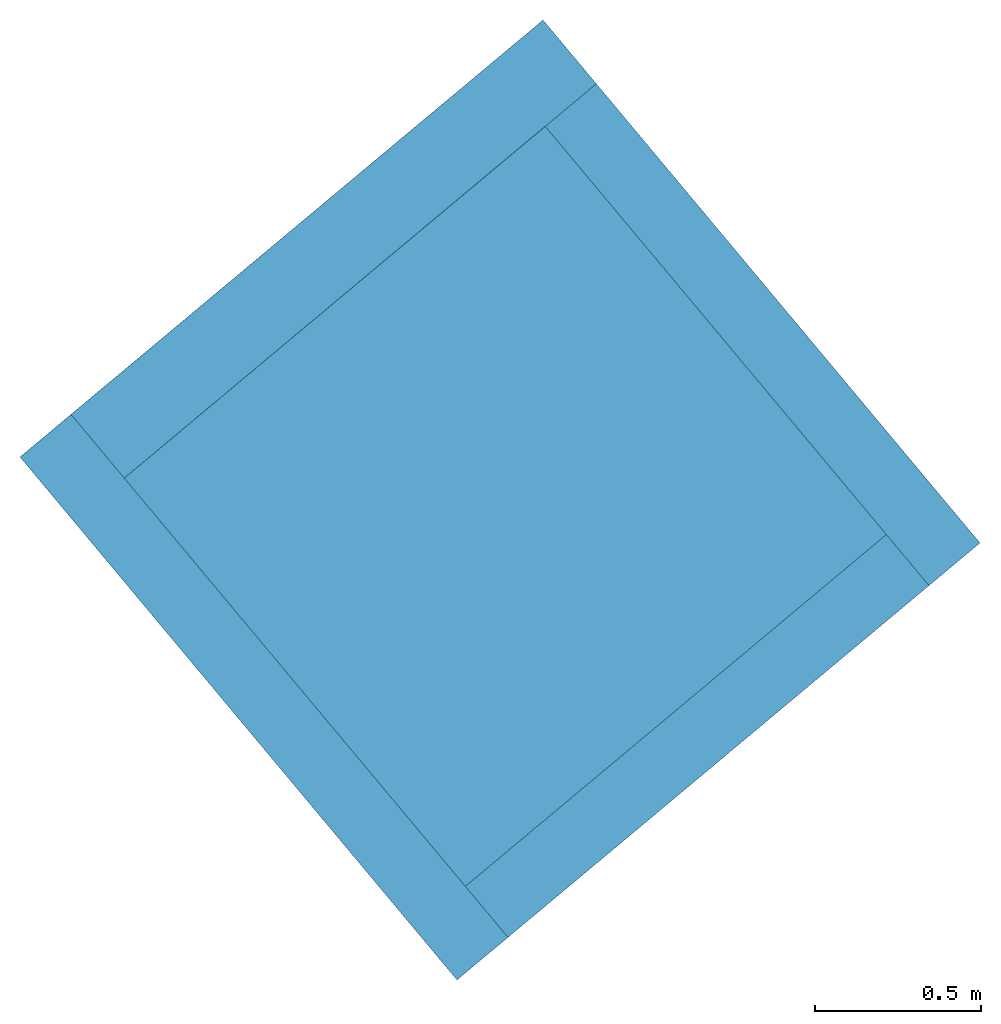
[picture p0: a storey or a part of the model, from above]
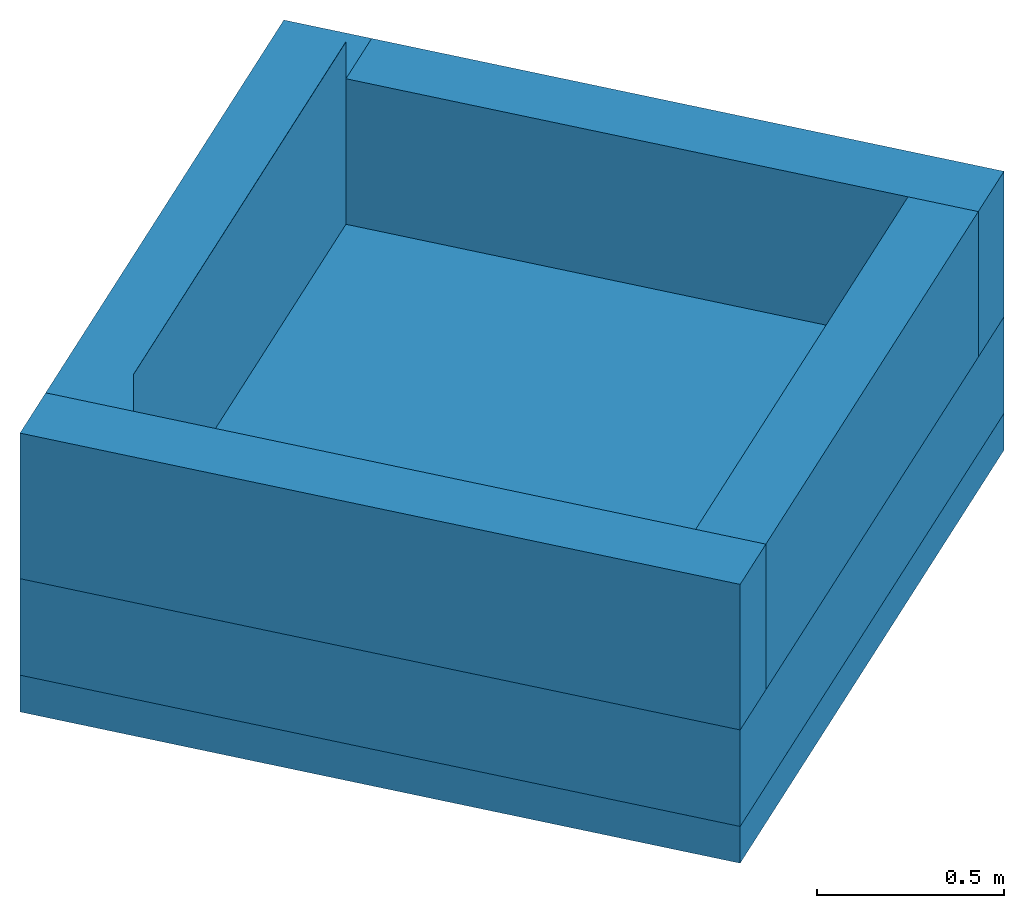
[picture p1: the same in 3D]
Properties of the parts of a building model (IFC4), part 1 of 2

# File
Description: ViewDefinition [ReferenceView_V1.2], ExchangeRequirement [Architecture], Option [Elements to export: Visible elements (on all stories)], Option [Partial Structure Display: Entire Model], Option [IFC Domain: All], Option [Structural Function: All Elements], Option [Convert Grid elements: On], Option [Convert IFC Annotations and Archicad 2D elements: Off], Option [Convert 2D symbols of Doors and Windows: Off], Option [Export geometries that Participates in Collision Detection only: Off], Option [Split complex elements: On], Option [IFC Domain For Space Containment: Custom], Option [IFC Model position: Survey Point and Project Origin], Option [Curtain Wall export mode: Single Element], Option [Railing export mode: Single Element], Option [Stair export mode: Single Element], Option [Properties To Export: All properties], Option [Space containment: Off], Option [Geometry to type objects: Off], Option [Element Properties: Off], Option [Building Material Properties: Off], Option [Element Parameters: Off], Option [Component Parameters: Off], Option [IFC Base Quantities: On], Option [Door Window Parameters: Off], Option [IFC Space boundaries: On], Option [Archicad Zone Categories as IFC Space classification data: Off], Option [Element Classifications: Off]
File name: Real-World-Escape-Route-Test-Model-ZDB-edited.ifc
Time: 2024-06-14T09:38:14
Author: Architect
Organization: Building Designer Office
Written by: The EXPRESS Data Manager Version 5.02.0100.09 : 26 Sep 2013
Made in: IFC file generated by Graphisoft Archicad 26.0.0 AUT FULL Windows version (IFC add-on version: 3001 AUT FULL).
Authorization: The authorising person

# IfcSite, Site
RefLatitude: 48, 14, 21, 681555; RefLongitude: 16, 25, 58, 549550; RefElevation: 159.13 m
Qto_SiteBaseQuantities - GrossPerimeter: 0 m; GrossArea: 0 m2

# IfcBuilding, Building
ZDB_BuildingData - BuildingClass: GK4
Qto_BuildingBaseQuantities - GrossFloorArea: 1661.32 m2

# IfcBuildingStorey (7)
In: Building
Name | Elevation (m) | AboveGround | NetHeight (m) = GrossHeight (m) | GrossFloorArea (m2)
UG2 | -4.295 | no | 0.995 | 2.64193
UG1 | -3.3 | no | 3.08 | 587.343
EG | -0.22 | yes | 2.96 | 344.876
OG1 | 2.74 | yes | 2.96 | 283.077
DG1 | 5.7 | yes | 2.96 | 254.499
DG2 | 8.66 | yes | 3.18 | 188.436 | ZDB_BuildingStoreyData - EscapeLevel: 8.66 m
DA | 11.84 | yes | 3 | 0.444092

# IfcSpace: Lagern, Verteilen und Verkaufen (5)
Pset_SpaceFireSafetyRequirements - FlammableStorage: no; SprinklerProtection: no
Pset_SpaceSpecific - HabitableRoom: no; LiveLoad: 2; Status: Neu
Pset_SpaceCommon - PubliclyAccessible: no
Pset_SpaceOccupancyRequirements - MinimumHeadroom: 2.5 m
ZDB_SpaceData - SpaceCategory: ND; UnitNumber: A01; StaircaseType: ND
Qto_SpaceBaseQuantities - FinishFloorHeight: 0 m
Name | In | LongName | AirPressurization = FireExit = IsExternal | FireRiskFactor | SpaceName | SpaceNumber | NutzflaechenTyp | WidmungBehoerde | HandicapAccessible | Brandabschnitt | OccupancyNumberPeak | NaturalVentilation | Height (m) = FinishCeilingHeight (m) | GrossFloorArea (m2) = NetFloorArea (m2) = GrossCeilingArea (m2) = NetCeilingArea (m2) | GrossWallArea (m2) | NetWallArea (m2) | GrossPerimeter (m) = NetPerimeter (m) | GrossVolume (m3) | NetVolume (m3)
A_1_U1_A01_014 | UG1 | KIWA | no | ND | Kinderwagen-Abstellraum | A_1_U1_A01_014 | Nebennutzflaeche | Sonstige Nutzungen | yes | Keller | 20 | no | 2.73 | 5.16775 | 25.2989 | 23.4989 | 9.45382 | 14.108 | 14.108
A_1_U1_A01_013 | UG1 | Einstellräume | no | ND | Einlagerungsraum | A_1_U1_A01_013 | Nebennutzflaeche | Sonstige Nutzungen | yes | Keller | 20 | no | 2.73 | 39.8056 | 76.8995 | 75.0995 | 29.8784 | 108.669 | 95.9139
A_1_U1_A01_015 | UG1 | E-Technik | no | C | … | A_1_U1_A01_015 | Technikflaeche | Betriebstechnische Anlagen | no | Keller | 20 | yes | 2.73 | 4.77207 | 22.91 | 19.31 | 8.76558 | 13.0278 | 13.0278
A_1_U1_A01_016 | UG1 | Haustechnik | no | C | … | A_1_U1_A01_016 | Technikflaeche | Betriebstechnische Anlagen | no | Keller | 20 | yes | 2.73 | 23.0212 | 55.6342 | 53.8342 | 21.7656 | 62.8479 | 62.8479
 | EG | Müll | yes | A | Müllraum | A_1_E0_A01_009 | KeineNutzflaeche | Sonstige Nutzungen | yes | ND | 2 | yes | 2.54 | 4.95081 | 30.0116 | 19.975 | 11.4309 | 12.575 | 12.575

# IfcSpace: Sanitärfläche (21)
Pset_SpaceFireSafetyRequirements - AirPressurization: no; FireExit: no; FireRiskFactor: ND; FlammableStorage: no; SprinklerProtection: no
Pset_SpaceSpecific - HabitableRoom: no; LiveLoad: 2; SpaceName: …; Status: Neu; NutzflaechenTyp: Nebennutzflaeche; WidmungBehoerde: Sanitär- und Umkleideräume
Pset_SpaceCommon - IsExternal: no; PubliclyAccessible: no
Pset_SpaceOccupancyRequirements - MinimumHeadroom: 2.5 m
Pset_SpaceThermalRequirements - NaturalVentilation: no
ZDB_SpaceData - SpaceCategory: Flat; StaircaseType: ND
Qto_SpaceBaseQuantities - FinishFloorHeight: 0 m
Name | In | LongName | SpaceNumber | HandicapAccessible | Brandabschnitt | OccupancyNumberPeak | UnitNumber | Height (m) = FinishCeilingHeight (m) | GrossFloorArea (m2) = NetFloorArea (m2) = GrossCeilingArea (m2) = NetCeilingArea (m2) | GrossWallArea (m2) | NetWallArea (m2) | GrossPerimeter (m) = NetPerimeter (m) | GrossVolume (m3) | NetVolume (m3)
 | EG | HW | A_1_E0_001_004 | no | E0_WohnungTOP1 | 2 | 001 | 2.54 | 2.96895 | 18.3322 | 16.7322 | 7.30403 | 7.54114 | 7.54114
 | EG | WC | A_1_E0_002_007 | no | E0_WohnungTOP2 | 1 | 002 | 2.54 | 1.82724 | 12.8637 | 11.2637 | 5.47374 | 4.64119 | 4.64119
 | EG | HW | A_1_E0_002_008 | no | E0_WohnungTOP2 | 2 | 002 | 2.54 | 2.76122 | 16.371 | 14.771 | 7.19922 | 7.0135 | 7.0135
 | EG | Bad | A_1_E0_002_004 | no | E0_WohnungTOP2 | 3 | 002 | 2.54 | 6.19331 | 26.0684 | 24.4684 | 10.3498 | 15.731 | 15.731
 | EG | Bad | A_1_E0_002_009 | no | E0_WohnungTOP2 | 3 | 002 | 2.54 | 5.01068 | 23.5844 | 21.9844 | 9.37183 | 12.7271 | 12.7271
 | EG | Bad | A_1_E0_001_003 | no | E0_WohnungTOP1 | 3 | 001 | 2.54 | 5.6085 | 25.3505 | 22.8805 | 10.1357 | 14.2456 | 14.2456
 | OG1 | HW | A_1_E1_003_004 | no | E1_WohnungTOP3 | 2 | 003 | 2.54 | 2.96895 | 18.3322 | 16.7322 | 7.30403 | 7.54114 | 7.54114
 | OG1 | WC | A_1_E1_004_007 | no | E1_WohnungTOP4 | 1 | 004 | 2.54 | 1.82724 | 12.8637 | 11.2637 | 5.47374 | 4.64119 | 4.64119
 | OG1 | HW | A_1_E1_004_008 | no | E1_WohnungTOP4 | 2 | 004 | 2.54 | 2.76122 | 16.371 | 14.771 | 7.19922 | 7.0135 | 7.0135
 | OG1 | Bad | A_1_E1_004_004 | yes | E1_WohnungTOP4 | 3 | 004 | 2.54 | 6.22359 | 26.4073 | 24.8073 | 10.5877 | 15.8079 | 15.8079
 | OG1 | Bad | A_1_E1_004_009 | no | E1_WohnungTOP4 | 3 | 004 | 2.54 | 7.12706 | 25.5604 | 23.9604 | 12.0948 | 18.1027 | 18.1027
 | OG1 | Bad | A_1_E1_003_003 | yes | E1_WohnungTOP3 | 3 | 003 | 2.54 | 7.33077 | 30.2902 | 27.2212 | 12.0122 | 18.6201 | 18.6201
 | DG1 | HW | A_1_E2_005_004 | no | E2_WohnungTOP05 | 2 | 005 | 2.54 | 2.965 | 18.3237 | 16.7237 | 7.30069 | 7.53111 | 7.53111
 | DG1 | WC | A_1_E2_006_006 | no | E2_WohnungTOP6 | 1 | 006 | 2.54 | 1.82724 | 12.8637 | 11.2637 | 5.47374 | 4.64119 | 4.64119
 | DG1 | HW | A_1_E2_006_007 | no | E2_WohnungTOP6 | 2 | 006 | 2.54 | 2.76122 | 16.371 | 14.771 | 7.19922 | 7.0135 | 7.0135
 | DG1 | Bad | A_1_E2_006_003 | yes | E2_WohnungTOP6 | 3 | 006 | 2.54 | 6.19423 | 25.8973 | 24.2973 | 10.3514 | 15.7333 | 15.7333
 | DG1 | Bad | A_1_E2_006_008 | no | E2_WohnungTOP6 | 3 | 006 | 2.54 | 5.01068 | 23.5844 | 20.5154 | 9.37183 | 12.7271 | 12.7271
 | DG1 | Bad | A_1_E2_005_003 | yes | E2_WohnungTOP5 | 3 | 005 | 2.54 | 5.6085 | 25.5241 | 22.4551 | 10.1357 | 14.2456 | 14.2456
 | DG2 | HW | A_1_E3_007_002 | no | E3_WohnungTOP07 | 2 | 007 | 2.76 | 6.50688 | 9.84566 | 9.84566 | 10.4796 | 17.959 | 17.959
 | DG2 | WC | A_1_E3_007_006 | no | E3_WohnungTOP7 | 1 | 007 | 2.76 | 1.89067 | 15.21 | 13.61 | 5.5906 | 5.21826 | 5.21826
 | DG2 | Bad | A_1_E3_007_005 | yes | E3_WohnungTOP07 | 3 | 007 | 2.76 | 14.145 | 15.5117 | 13.9117 | 16.9425 | 39.0402 | 23.9196

# IfcSpace: Sonstige Nutzungen (10)
Pset_SpaceFireSafetyRequirements - AirPressurization: no; FireExit: no; FireRiskFactor: A; FlammableStorage: no; SprinklerProtection: no
Pset_SpaceSpecific - HabitableRoom: no; LiveLoad: 4; SpaceName: …; Status: Neu; NutzflaechenTyp: Nebennutzflaeche; WidmungBehoerde: Terrassen, Balkone
Pset_SpaceCommon - HandicapAccessible: no; IsExternal: yes; PubliclyAccessible: no
Pset_SpaceOccupancyRequirements - MinimumHeadroom: 2.5 m
Pset_SpaceThermalRequirements - NaturalVentilation: yes
ZDB_SpaceData - SpaceCategory: Flat; StaircaseType: ND
Qto_SpaceBaseQuantities - FinishFloorHeight: 0 m
Name | In | LongName | SpaceNumber | Brandabschnitt | OccupancyNumberPeak | UnitNumber | Height (m) = FinishCeilingHeight (m) | GrossFloorArea (m2) = NetFloorArea (m2) = GrossCeilingArea (m2) = NetCeilingArea (m2) | GrossWallArea (m2) | NetWallArea (m2) | GrossPerimeter (m) = NetPerimeter (m) | GrossVolume (m3) | NetVolume (m3)
 | EG | Terrasse | A_1_E0_A01_010 | E0_WohnungTOP02 | 10 | 002 | 2.76 | 52.676 | 57.2332 | 33.1281 | 56.9358 | 145.386 | 145.386
 | EG | Terrasse | A_1_E0_A01_009 | E0_WohnungTOP01 | 10 | 001 | 2.76 | 36.3547 | 0 | 0 | 29.0911 | 100.339 | 93.23
 | EG | Terrasse | A_1_E0_A01_010 | E0_WohnungTOP01 | 10 | 001 | 2.54 | 7.99865 | 0.54077 | 0.54077 | 12.388 | 20.3166 | 20.3166
 | OG1 | Balkon | A_1_E1_A01_009 | E2_WohnungTOP03 | 6 | 003 | 2.54 | 7.2141 | 18.5206 | 15.221 | 13.7896 | 18.3238 | 25.4018
 | OG1 | Balkon | A_1_E1_A01_009 | E1_WohnungTOP02 | 6 | 004 | 2.54 | 16.0176 | 27.763 | 19.9299 | 21.3914 | 40.6848 | 52.0922
 | DG1 | Balkon | A_1_E2_A01_009 | E2_WohnungTOP05 | 6 | 005 | 2.74 | 7.05397 | 17.0496 | 13.75 | 13.4596 | 19.3279 | 27.486
 | DG1 | Balkon | A_1_E2_A01_010 | E2_WohnungTOP06 | 10 | 006 | 1 | 28.8045 | 18.7301 | 14.965 | 23.3022 | 28.8045 | 32.7364
 | DG2 | Terrasse | A_1_E3_A01_006 | E3_WohnungTOP07 | 6 | 007 | 2.96 | 4.84106 | 21.6911 | 17.6231 | 12.0095 | 14.3296 | 24.1949
 | DG2 | Terrasse | A_1_E3_A01_007 | E3_WohnungTOP07 | 6 | 007 | 2.96 | 18.6552 | 31.223 | 25.4238 | 20.52 | 55.2192 | 70.5757
 | DG2 | Terrasse | A_1_E3_A01_008 | E3_WohnungTOP07 | 6 | 007 | 2.96 | 5.38649 | 20.9787 | 14.8767 | 12.0191 | 15.944 | 28.3088

# IfcSpace: Unverwendbare Grundfläche (19)
Pset_SpaceFireSafetyRequirements - AirPressurization: no; FireExit: no; FireRiskFactor: ND; FlammableStorage: no; SprinklerProtection: no
Pset_SpaceSpecific - HabitableRoom: no; LiveLoad: 0; SpaceName: …; Status: Neu; NutzflaechenTyp: KeineNutzflaeche; WidmungBehoerde: Betriebstechnische Anlagen
Pset_SpaceCommon - HandicapAccessible: no; IsExternal: no; PubliclyAccessible: no
Pset_SpaceOccupancyRequirements - MinimumHeadroom: 0 m; OccupancyNumberPeak: 0
Pset_SpaceThermalRequirements - NaturalVentilation: no
ZDB_SpaceData - SpaceCategory: ND; StaircaseType: ND
Qto_SpaceBaseQuantities - FinishFloorHeight: 0 m
Name | In | LongName | SpaceNumber | Brandabschnitt | UnitNumber | Height (m) = FinishCeilingHeight (m) | GrossFloorArea (m2) = NetFloorArea (m2) = GrossCeilingArea (m2) = NetCeilingArea (m2) | GrossWallArea (m2) = NetWallArea (m2) | GrossPerimeter (m) = NetPerimeter (m) | GrossVolume (m3) | NetVolume (m3)
 | EG | Schacht 5 | A_1_E0_A01_008 | E0_Schacht05 | A01 | 2.96 | 0.282848 | 6.64354 | 2.30208 | 0.83723 | 0.83723
 | EG | Schacht 4 | A_1_E0_A01_007 | E0_Schacht01 | A01 | 2.96 | 0.474273 | 8.80521 | 3.19029 | 1.40385 | 1.40385
 | EG | Schacht 2 | A_1_E0_A01_005 | E0_Schacht02 | A01 | 2.96 | 0.222581 | 6.31989 | 2.28981 | 0.658841 | 0.658841
 | EG | Schacht 3 | A_1_E0_A01_004 | E0_Schacht03 | A01 | 2.96 | 0.431564 | 11.7511 | 4.58426 | 1.27743 | 1.27743
 | EG | Schacht 1 | A_1_E0_A01_006 | E0_Schacht01 | A01 | 2.96 | 0.428025 | 8.67996 | 3.14491 | 1.26696 | 1.26696
 | OG1 | Schacht 5 | A_1_E1_A01_008 | E0_Schacht05 | A01 | 2.96 | 0.282848 | 6.64354 | 2.30208 | 0.83723 | 0.83723
 | OG1 | Schacht 4 | A_1_E1_A01_007 | E0_Schacht01 | A01 | 2.96 | 0.474273 | 8.80521 | 3.19029 | 1.40385 | 1.40385
 | OG1 | Schacht 2 | A_1_E1_A01_005 | E0_Schacht02 | A01 | 2.96 | 0.222581 | 6.31989 | 2.28981 | 0.658841 | 0.658841
 | OG1 | Schacht 3 | A_1_E1_A01_004 | E0_Schacht03 | A01 | 2.96 | 0.431637 | 11.6442 | 4.58434 | 1.27765 | 1.27765
 | OG1 | Schacht 1 | A_1_E1_A01_006 | E0_Schacht01 | A01 | 2.96 | 0.428025 | 8.67996 | 3.14491 | 1.26696 | 1.26696
 | DG1 | Schacht 5 | A_1_E2_A01_008 | E0_Schacht05 | A01 | 2.96 | 0.282848 | 6.64354 | 2.30208 | 0.83723 | 0.83723
 | DG1 | Schacht 4 | A_1_E2_A01_007 | E0_Schacht01 | A01 | 2.96 | 0.474273 | 8.80521 | 3.19029 | 1.40385 | 1.40385
 | DG1 | Schacht 2 | A_1_E2_A01_005 | E0_Schacht02 | A01 | 2.96 | 0.222581 | 6.31989 | 2.28981 | 0.658841 | 0.658841
 | DG1 | Schacht 3 | A_1_E2_A01_004 | E0_Schacht03 | A01 | 2.74 | 0.430623 | 11.6412 | 4.58316 | 1.17991 | 1.17989
 | DG1 | Schacht 1 | A_1_E2_A01_006 | E0_Schacht01 | A01 | 2.96 | 0.427249 | 8.66771 | 3.14048 | 1.26466 | 1.26466
 | DG2 | Schacht | A_1_E3_A01_005 | E3_Schacht02 |  | 3.18 | 1.02716 | 21.9158 | 10.8274 | 3.26636 | 2.24284
 | DG2 | Schacht | A_1_E3_A01_004 | E3_Schacht01 | A01 | 3.18 | 0.174283 | 5.105 | 1.71309 | 0.55422 | 0.55422
 | DA | Schacht | A_1_E2_A01_007 | E0_Schacht01 |  | 1 | 0.174283 | 1.71309 | 1.71309 | 0.174283 | 0.174283
 | DA | Schacht | A_1_E2_A01_007 | E0_Schacht01 |  | 1 | 0.269809 | 3.01571 | 3.01571 | 0.269809 | 0.269809

# IfcSpace: Verkehrserschl. und -sicherung (12)
Pset_SpaceFireSafetyRequirements - FlammableStorage: no; SprinklerProtection: no
Pset_SpaceSpecific - HabitableRoom: no; Status: Neu; NutzflaechenTyp: Verkehrsflaeche; WidmungBehoerde: Verkehrserschliessung und -sicherung
Pset_SpaceCommon - IsExternal: no; PubliclyAccessible: no
Qto_SpaceBaseQuantities - FinishFloorHeight: 0 m
Name | In | LongName | AirPressurization | FireExit | FireRiskFactor | LiveLoad | SpaceName | SpaceNumber | HandicapAccessible | Brandabschnitt | MinimumHeadroom (m) | OccupancyNumberPeak | NaturalVentilation | SpaceCategory | StaircaseType | Height (m) = FinishCeilingHeight (m) | GrossFloorArea (m2) = GrossCeilingArea (m2) | NetFloorArea (m2) = NetCeilingArea (m2) | GrossWallArea (m2) | NetWallArea (m2) | GrossPerimeter (m) = NetPerimeter (m) | GrossVolume (m3) | NetVolume (m3) | UnitNumber
 | UG2 | Aufzug | yes | no | A | 2 | Aufzug | A_1_U2_A01_001 | yes | Stiegenhaus | 2.5 | 12 | no | ND | ND | 0.995 | 2.64193 | 2.64193 | 2.52645 | 2.52645 | 6.50238 | 2.62872 | 2.62872
A_1_U1_A01_010 | UG1 | Garage | no | no | F | 5 | EinstellraumParkeinrichtung | A_1_U1_A01_010 | yes | Garage | 2.1 | 20 | yes | Traffic area | ND | 2.75 | 235.551 | 235.553 | 159.545 | 157.745 | 82.969 | 647.765 | 647.77 | A01
 | UG1 | Aufzug | yes | no | A | 2 | Aufzug | A_1_U1_A01_012 | yes | Stiegenhaus | 2.5 | 12 | no | ND | ND | 2.88 | 2.64111 | 2.64111 | 18.418 | 15.998 | 6.50139 | 7.6064 | 7.6064 | A01
A_1_U1_A01_009 | UG1 | Rampe | no | no | ND | 5 | Einfahrt | A_1_U1_A01_009 | no | Garage | 2.1 | 20 | no | Traffic area | ND | 3.08 | 95.0264 | 95.0264 | 130.961 | 130.961 | 59.8101 | 292.681 | 163.093 | A01
A_1_U1_A01_011 | UG1 | Gang | yes | yes | A | 2 | Treppenhaus | A_1_U1_A01_011 | no | Stiegenhaus | 2.5 | 0 | yes | Connection room | OIB2Tab2ab | 2.75 | 8.23629 | 8.23629 | 23.0528 | 13.4328 | 13.6368 | 22.6498 | 22.6498 | A01
 | EG | Aufzug | yes | no | ND | 2 | … | A_1_E0_A01_002 | no | Stiegenhaus | 2.5 | 12 | no | ND | ND | 2.96 | 2.63383 | 2.63383 | 12.8028 | 10.3828 | 6.49253 | 7.79614 | 7.79614 | A01
 | OG1 | Aufzug | yes | no | ND | 2 | … | A_1_E1_A01_002 | no | Stiegenhaus | 2.5 | 12 | no | ND | ND | 2.96 | 2.63383 | 2.63383 | 17.3582 | 14.9382 | 6.49253 | 7.79614 | 7.79614 | A01
A_1_E1_A01_003 | OG1 | Treppenlauf | yes | yes | A | 2 | Treppenhaus | A_1_E1_A01_003 | yes | Stiegenhaus | 2.5 | 20 | yes | Connection room | OIB2Tab2ab | 2.54 | 8.8324 | 8.8324 | 24.1321 | 24.1321 | 12.5631 | 22.4343 | 22.4343 | A01
A_1_E2_A01_003 | DG1 | Treppenlauf | yes | yes | A | 2 | Treppe | A_1_E2_A01_003 | yes | Stiegenhaus | 2.5 | 20 | yes | Connection room | OIB2Tab2ab | 2.54 | 8.8324 | 8.8324 | 23.7415 | 23.7415 | 12.5631 | 22.4343 | 22.4343 | A01
 | DG1 | Aufzug | yes | no | ND | 2 | … | A_1_E2_A01_002 | no | Stiegenhaus | 2.5 | 12 | no | ND | ND | 2.96 | 2.63383 | 2.63383 | 4.53949 | 4.53949 | 6.49253 | 7.79614 | 7.79614 | A01
 | DG2 | Aufzug | yes | no | ND | 2 | … | A_1_E3_A01_002 | no | Stiegenhaus | 2.5 | 12 | no | ND | ND | 3.93 | 2.63383 | 2.63383 | 6.46019 | 6.46019 | 6.49253 | 10.351 | 10.351 | A01
A_1_E3_A01_003 | DG2 | Treppenlauf | yes | yes | A | 2 | Treppenhaus | A_1_E3_A01_003 | yes | Stiegenhaus | 2.5 | 20 | yes | Connection room | OIB2Tab2ab | 2.76 | 10.3975 | 10.3975 | 7.57101 | 7.57101 | 13.4032 | 28.697 | 28.697 | A01

# IfcSpace: Verkehrserschl. und -sicherung (8)
In: UG1
Type - PredefinedType: INTERNAL
LongName: Stellplatz
Pset_SpaceSpecific - SpaceName: Stellplatz; Status: Neu; WidmungBehoerde: Sonstige Nutzungen
Pset_SpaceCommon - HandicapAccessible: no; IsExternal: no; PubliclyAccessible: no
Pset_SpaceOccupancyRequirements - MinimumHeadroom: 2.1 m
ZDB_SpaceData - SpaceCategory: Traffic area; UnitNumber: A01; StaircaseType: ND
Qto_SpaceBaseQuantities - Height: 2.73 m; FinishCeilingHeight: 2.73 m; FinishFloorHeight: 0 m
Name | SpaceNumber | GrossFloorArea (m2) = GrossCeilingArea (m2) | NetFloorArea (m2) = NetCeilingArea (m2) | GrossWallArea (m2) = NetWallArea (m2) | GrossPerimeter (m) = NetPerimeter (m) | GrossVolume (m3) | NetVolume (m3)
A_1_U1_A01_003 | A_1_U1_A01_003 | 14.3784 | 14.3784 | 11.217 | 16.5993 | 39.2531 | 39.2531
A_1_U1_A01_004 | A_1_U1_A01_004 | 14.2172 | 14.2172 | 7.37296 | 16.2478 | 38.8129 | 38.8129
A_1_U1_A01_008 | A_1_U1_A01_008 | 15.6533 | 15.6535 | 5.62424 | 16.9235 | 42.7335 | 42.7341
A_1_U1_A01_005 | A_1_U1_A01_005 | 15.1043 | 15.1043 | 7.77931 | 16.3002 | 41.2347 | 41.2347
A_1_U1_A01_001 | A_1_U1_A01_001 | 14.6835 | 14.6835 | 7.56259 | 16.1415 | 40.0859 | 40.0859
A_1_U1_A01_006 | A_1_U1_A01_006 | 15.902 | 15.902 | 0 | 16.6012 | 43.4125 | 43.4125
A_1_U1_A01_007 | A_1_U1_A01_007 | 14.2172 | 14.2172 | 1.98371 | 16.2474 | 38.8128 | 38.8128
A_1_U1_A01_002 | A_1_U1_A01_002 | 14.4765 | 14.4765 | 9.49963 | 16.3552 | 39.5208 | 39.5208

# IfcSpace: Wohnen und Aufenthalt (36)
Pset_SpaceFireSafetyRequirements - FlammableStorage: no; SprinklerProtection: no
Pset_SpaceSpecific - LiveLoad: 2; Status: Neu
Pset_SpaceCommon - IsExternal: no; PubliclyAccessible: no
Pset_SpaceOccupancyRequirements - MinimumHeadroom: 2.5 m
Qto_SpaceBaseQuantities - FinishFloorHeight: 0 m
Name | In | LongName | AirPressurization = FireExit | FireRiskFactor | HabitableRoom | SpaceName | SpaceNumber | NutzflaechenTyp | WidmungBehoerde | HandicapAccessible = NaturalVentilation | Brandabschnitt | OccupancyNumberPeak | SpaceCategory | UnitNumber | StaircaseType | Height (m) = FinishCeilingHeight (m) | GrossFloorArea (m2) = NetFloorArea (m2) = GrossCeilingArea (m2) = NetCeilingArea (m2) | GrossWallArea (m2) | NetWallArea (m2) | GrossPerimeter (m) = NetPerimeter (m) | GrossVolume (m3) | NetVolume (m3)
A_1_E0_A01_003 | UG1 | Treppenlauf | yes | A | no | Treppenhaus | A_1_E0_A01_003 | Verkehrsflaeche | Verkehrserschliessung und -sicherung | yes | Stiegenhaus | 20 | Connection room | A01 | OIB2Tab2ab | 2.86354 | 8.48762 | 16.4523 | 16.4523 | 12.0526 | 24.3046 | 24.3046
 | EG | Zimmer | no | ND | yes | Wohnen | A_1_E0_002_002 | Hauptnutzflaeche | Wohnen und Aufenthalt | yes | E0_WohnungTOP2 | 3 | Flat | 002 | ND | 2.54 | 13.4653 | 37.7732 | 32.1052 | 15.2147 | 34.2017 | 34.2017
 | EG | Zimmer | no | ND | yes | Wohnen | A_1_E0_002_003 | Hauptnutzflaeche | Wohnen und Aufenthalt | yes | E0_WohnungTOP2 | 3 | Flat | 002 | ND | 2.54 | 13.4869 | 37.8001 | 32.1321 | 15.2252 | 34.2567 | 34.2567
 | EG | Zimmer | no | ND | yes | Wohnen | A_1_E0_002_010 | Hauptnutzflaeche | Wohnen und Aufenthalt | yes | E0_WohnungTOP2 | 3 | Flat | 002 | ND | 2.54 | 15.6508 | 39.6669 | 31.9649 | 16.1815 | 39.7529 | 39.7529
 | EG | Wohnküche | no | F | yes | Wohnküche | A_1_E0_001_005 | Hauptnutzflaeche | Wohnen und Aufenthalt | yes | E0_WohnungTOP1 | 10 | Flat | 001 | ND | 2.54 | 34.1284 | 56.0788 | 48.2995 | 23.954 | 86.6862 | 86.6862
 | EG | Vorr. | no | ND | no | … | A_1_E0_002_001 | Nebennutzflaeche | Wohnen und Aufenthalt | no | E0_WohnungTOP2 | 10 | Flat | 002 | ND | 2.54 | 10.6606 | 44.5507 | 36.1507 | 18.0887 | 27.0779 | 27.0779
A_1_E0_A01_001 | EG | Gang | yes | A | no | Treppenhaus | A_1_E0_A01_001 | Verkehrsflaeche | Verkehrserschliessung und -sicherung | yes | Stiegenhaus | 20 | Connection room | A01 | OIB2Tab2ab | 2.54 | 7.90334 | 24.6689 | 16.1709 | 13.1972 | 20.0745 | 20.0745
 | EG | Gang | no | ND | no | … | A_1_E0_002_006 | Nebennutzflaeche | Wohnen und Aufenthalt | no | E0_WohnungTOP2 | 5 | Flat | 002 | ND | 2.61 | 3.23075 | 18.2181 | 10.0181 | 7.7869 | 8.43226 | 8.43226
 | EG | Vorr. | no | ND | no | … | A_1_E0_001_001 | Nebennutzflaeche | Wohnen und Aufenthalt | no | E0_WohnungTOP1 | 6 | Flat | 001 | ND | 2.54 | 8.4293 | 36.6349 | 28.2349 | 14.8525 | 21.4104 | 21.4104
 | EG | Zimmer | no | ND | yes | Wohnen | A_1_E0_001_002 | Hauptnutzflaeche | Wohnen und Aufenthalt | yes | E0_WohnungTOP1 | 3 | Flat | 001 | ND | 2.61 | 14.5779 | 38.7488 | 33.0808 | 16.0227 | 38.0484 | 38.0484
 | EG | Wohnküche | no | F | yes | Wohnküche | A_1_E0_002_005 | Hauptnutzflaeche | Wohnen und Aufenthalt | yes | E0_WohnungTOP2 | 10 | Flat | 002 | ND | 2.54 | 34.3452 | 55.3543 | 41.8872 | 24.3401 | 87.2367 | 87.2367
A_1_E0_A01_003 | EG | Treppenlauf | yes | A | no | Treppenhaus | A_1_E0_A01_003 | Verkehrsflaeche | Verkehrserschliessung und -sicherung | yes | Stiegenhaus | 20 | Connection room | A01 | OIB2Tab2ab | 2.54 | 8.48762 | 23.4097 | 23.4097 | 12.0526 | 21.5586 | 21.5586
 | OG1 | Zimmer | no | ND | yes | Wohnen | A_1_E1_004_002 | Hauptnutzflaeche | Wohnen und Aufenthalt | yes | E1_WohnungTOP4 | 3 | Flat | 004 | ND | 2.54 | 13.4653 | 38.4252 | 32.7572 | 15.2147 | 34.2017 | 34.2017
 | OG1 | Zimmer | no | ND | yes | Wohnen | A_1_E1_004_003 | Hauptnutzflaeche | Wohnen und Aufenthalt | yes | E1_WohnungTOP4 | 3 | Flat | 004 | ND | 2.54 | 13.4869 | 37.8001 | 32.1321 | 15.2252 | 34.2567 | 34.2567
 | OG1 | Zimmer | no | ND | yes | Wohnen | A_1_E1_004_010 | Hauptnutzflaeche | Wohnen und Aufenthalt | yes | E1_WohnungTOP4 | 3 | Flat | 004 | ND | 2.54 | 20.0078 | 39.6684 | 31.9664 | 18.9044 | 50.8198 | 50.8198
 | OG1 | Wohnküche | no | F | yes | Wohnküche | A_1_E1_003_005 | Hauptnutzflaeche | Wohnen und Aufenthalt | yes | E1_WohnungTOP3 | 10 | Flat | 003 | ND | 2.54 | 34.1284 | 56.3947 | 45.1931 | 23.954 | 86.6862 | 86.6862
 | OG1 | Vorr. | no | ND | no | … | A_1_E1_004_001 | Nebennutzflaeche | Wohnen und Aufenthalt | no | E1_WohnungTOP4 | 10 | Flat | 004 | ND | 2.54 | 10.6598 | 40.399 | 31.999 | 17.8777 | 27.076 | 27.076
A_1_E1_A01_001 | OG1 | Gang | yes | A | no | Treppenhaus | A_1_E1_A01_001 | Verkehrsflaeche | Verkehrserschliessung und -sicherung | yes | Stiegenhaus | 20 | Connection room | A01 | OIB2Tab2ab | 2.54 | 7.55856 | 24.2686 | 15.8756 | 13.1389 | 19.1987 | 19.1987
 | OG1 | Gang | no | ND | no | … | A_1_E1_004_006 | Nebennutzflaeche | Wohnen und Aufenthalt | no | E1_WohnungTOP4 | 5 | Flat | 004 | ND | 2.39 | 3.23075 | 17.5059 | 9.30594 | 7.7869 | 7.72149 | 7.72149
 | OG1 | Vorr. | no | ND | no | … | A_1_E1_003_001 | Nebennutzflaeche | Wohnen und Aufenthalt | no | E1_WohnungTOP3 | 6 | Flat | 003 | ND | 2.54 | 8.4293 | 36.6349 | 28.2349 | 14.8525 | 21.4104 | 21.4104
 | OG1 | Zimmer | no | ND | yes | Wohnen | A_1_E1_003_002 | Hauptnutzflaeche | Wohnen und Aufenthalt | yes | E1_WohnungTOP3 | 3 | Flat | 003 | ND | 2.54 | 18.5005 | 43.723 | 38.055 | 17.8991 | 46.9912 | 46.9912
 | OG1 | Wohnküche | no | F | yes | Wohnküche | A_1_E1_004_005 | Hauptnutzflaeche | Wohnen und Aufenthalt | yes | E1_WohnungTOP4 | 10 | Flat | 004 | ND | 2.54 | 42.1786 | 61.9748 | 48.5077 | 26.4699 | 107.134 | 107.134
 | DG1 | Zimmer | no | ND | yes | Wohnen | A_1_E2_006_002 | Hauptnutzflaeche | Wohnen und Aufenthalt | yes | E2_WohnungTOP6 | 3 | Flat | 006 | ND | 2.54 | 15.4877 | 7.98936 | 6.38936 | 16.0566 | 39.3386 | 31.8295
 | DG1 | Zimmer | no | ND | yes | Wohnen | A_1_E2_006_009 | Hauptnutzflaeche | Wohnen und Aufenthalt | yes | E2_WohnungTOP6 | 3 | Flat | 006 | ND | 2.54 | 15.6508 | 40.8809 | 33.1789 | 16.1815 | 39.7529 | 39.7529
 | DG1 | Wohnküche | no | F | yes | Wohnküche | A_1_E2_005_005 | Hauptnutzflaeche | Wohnen und Aufenthalt | yes | E2_WohnungTOP5 | 10 | Flat | 005 | ND | 2.54 | 32.7169 | 40.5724 | 29.3708 | 23.9445 | 83.1008 | 83.1008
 | DG1 | Vorr. | no | ND | no | … | A_1_E2_006_001 | Nebennutzflaeche | Wohnen und Aufenthalt | no | E2_WohnungTOP6 | 10 | Flat | 006 | ND | 2.54 | 10.6665 | 44.2496 | 37.4496 | 17.8835 | 27.0929 | 27.0929
A_1_E2_A01_001 | DG1 | Gang | yes | A | no | Treppenhaus | A_1_E2_A01_001 | Verkehrsflaeche | Verkehrserschliessung und -sicherung | yes | Stiegenhaus | 20 | Connection room | A01 | OIB2Tab2ab | 2.54 | 7.56248 | 23.3794 | 14.9864 | 13.1405 | 19.2087 | 19.2087
 | DG1 | Gang | no | ND | no | … | A_1_E2_006_005 | Nebennutzflaeche | Wohnen und Aufenthalt | no | E1_WohnungTOP4 | 5 | Flat | 006 | ND | 2.39 | 3.23075 | 17.5059 | 9.30594 | 7.7869 | 7.72149 | 7.72149
 | DG1 | Vorr. | no | ND | no | … | A_1_E2_005_001 | Nebennutzflaeche | Wohnen und Aufenthalt | no | E2_WohnungTOP5 | 6 | Flat | 005 | ND | 2.54 | 8.42722 | 27.4022 | 20.8022 | 14.8503 | 21.4051 | 21.4051
 | DG1 | Zimmer | no | ND | yes | Wohnen | A_1_E2_005_002 | Hauptnutzflaeche | Wohnen und Aufenthalt | yes | E2_WohnungTOP5 | 3 | Flat | 005 | ND | 2.54 | 14.5779 | 0 | 0 | 16.0227 | 37.0279 | 28.0754
 | DG1 | Wohnküche | no | F | yes | Wohnküche | A_1_E2_006_004 | Hauptnutzflaeche | Wohnen und Aufenthalt | yes | E2_WohnungTOP6 | 10 | Flat | 006 | ND | 2.54 | 34.7137 | 63.404 | 49.9368 | 27.0313 | 88.1727 | 88.1727
A_1_E3_A01_001 | DG2 | Gang | yes | A | no | Treppenhaus | A_1_E3_A01_001 | Verkehrsflaeche | Verkehrserschliessung und -sicherung | yes | Stiegenhaus | 20 | Connection room | A01 | OIB2Tab2ab | 2.76 | 5.68898 | 5.46161 | 3.36161 | 10.4905 | 15.7016 | 12.914
 | DG2 | Wohnküche | no | F | yes | Wohnküche | A_1_E3_007_007 | Hauptnutzflaeche | Wohnen und Aufenthalt | yes | E3_WohnungTOP07 | 10 | Flat | 007 | ND | 2.76 | 42.0555 | 58.0663 | 42.5312 | 27.0246 | 116.073 | 114.464
 | DG2 | Gang | no | A | no | … | A_1_E3_007_001 | Nebennutzflaeche | Wohnen und Aufenthalt | no | E3_WohnungTOP07 | 10 | Flat | 007 | ND | 2.76 | 12.0528 | 42.8074 | 34.8074 | 20.2618 | 33.2658 | 31.0654
 | DG2 | Zimmer | no | ND | yes | Wohnen | A_1_E3_007_004 | Hauptnutzflaeche | Wohnen und Aufenthalt | yes | E3_WohnungTOP07 | 3 | Flat | 007 | ND | 2.76 | 19.2049 | 48.066 | 40.364 | 17.7312 | 53.0056 | 53.0056
 | DG2 | Zimmer | no | ND | yes | Wohnen | A_1_E3_007_003 | Hauptnutzflaeche | Wohnen und Aufenthalt | yes | E3_WohnungTOP07 | 3 | Flat | 007 | ND | 2.76 | 17.1958 | 30.2305 | 28.6305 | 17.2084 | 47.4604 | 32.7502

# IfcBeam: Stahlbeton 415 x 430, Träger-001
In: UG1
Material: Stahlbeton
Pset_BeamCommon - Brandwiderstand: R 90; FireRating: R 90; IsExternal: yes; LoadBearing: yes; Status: Neu
Qto_BeamBaseQuantities - Length: 17.4084 m; CrossSectionArea: 0.17845 m2; OuterSurfaceArea: 21.906 m2; GrossSurfaceArea: 22.2629 m2; GrossVolume: 3.15112 m3; NetSurfaceArea: 22.2629 m2; NetVolume: 2.40255 m3

# IfcBeam: Stahlbeton 800 x 500 (2)
In: EG
Material: Stahlbeton
Pset_BeamCommon - Brandwiderstand: R 90; FireRating: R 90; IsExternal: no; LoadBearing: yes; Status: Neu
Qto_BeamBaseQuantities - CrossSectionArea: 0.4 m2
Name | Length (m) | OuterSurfaceArea (m2) | GrossSurfaceArea (m2) = NetSurfaceArea (m2) | GrossVolume (m3) | NetVolume (m3)
Träger-001 | 6.74396 | 17.2093 | 18.0093 | 2.69758 | 2.64759
Träger-002 | 6.74822 | 17.2204 | 18.0204 | 2.69929 | 2.64929

# IfcBeam: Stahlbeton 800 x 730 (2)
In: EG
Material: Stahlbeton
Pset_BeamCommon - IsExternal: no; LoadBearing: yes; Status: Neu
Qto_BeamBaseQuantities - CrossSectionArea: 0.584 m2
Name | Brandwiderstand = FireRating | Length (m) | OuterSurfaceArea (m2) | GrossSurfaceArea (m2) = NetSurfaceArea (m2) | GrossVolume (m3) | NetVolume (m3)
Träger-001 | R 90 | 7.38631 | 22.602 | 23.77 | 4.3136 | 4.31359
Träger-001 | REI 90 | 7.39121 | 22.617 | 23.785 | 4.31647 | 4.31645

# IfcBuildingElementPart (2504)
Name | In | Material
WU-Beton | UG2 | WU-Beton
Stampfbeton | UG2 | Stampfbeton
107 x BEKLEIDUNG | UG1 | BEKLEIDUNG
7 x Stahlbeton Decke | UG1 | Stahlbeton Decke
2 x Asphalt | UG1 | Asphalt
4 x Sperrschicht | UG1 | Sperrschicht
2 x XPS | UG1 | XPS
9 x Zementputz | UG1 | Zementputz
3 x Stahlbeton Wand | UG1 | Stahlbeton Wand
4 x XPS KG | UG1 | XPS KG
2 x Kalkzementputz KG | UG1 | Kalkzementputz KG
Mineralwolle weich | UG1 | Mineralwolle weich
Gipskarton | UG1 | Gipskarton
2 x WU-Beton | UG1 | WU-Beton
2 x Stampfbeton | UG1 | Stampfbeton
7 x Holzwolledämmplatte | UG1 | Holzwolledämmplatte
2 x Stahlbeton Decke Garage | UG1 | Stahlbeton Decke Garage
Fliesen | UG1 | Fliesen
105 x BEKLEIDUNG | EG | BEKLEIDUNG
3 x Stahlbeton Decke | EG | Stahlbeton Decke
37 x Mineralwolle weich | EG | Mineralwolle weich
66 x Gipskarton | EG | Gipskarton
10 x Stahlbeton Wand | EG | Stahlbeton Wand
8 x Zementputz | EG | Zementputz
4 x EPS 1 | EG | EPS 1
97 x Aluminium | EG | Aluminium
52 x Zaun | EG | Zaun
2 x Gipsputz | EG | Gipsputz
6 x Parkett | EG | Parkett
16 x Estrich | EG | Estrich
16 x Trittschalldämmung | EG | Trittschalldämmung
16 x Schüttung | EG | Schüttung
10 x Fliesen | EG | Fliesen
11 x Profilit | EG | Profilit
65 x Gipskarton | OG1 | Gipskarton
37 x Mineralwolle weich | OG1 | Mineralwolle weich
2 x Gipsputz | OG1 | Gipsputz
28 x Zementputz | OG1 | Zementputz
20 x EPS 1 | OG1 | EPS 1
16 x Stahlbeton Wand | OG1 | Stahlbeton Wand
6 x Parkett | OG1 | Parkett
16 x Estrich | OG1 | Estrich
16 x Trittschalldämmung | OG1 | Trittschalldämmung
16 x Schüttung | OG1 | Schüttung
10 x Fliesen | OG1 | Fliesen
105 x BEKLEIDUNG | OG1 | BEKLEIDUNG
3 x Stahlbeton Decke | OG1 | Stahlbeton Decke
16 x Vollholz | OG1 | Vollholz
8 x Brettschichtholz | OG1 | Brettschichtholz
8 x Stahlbeton | OG1 | Stahlbeton
8 x Holzwerkstoff | OG1 | Holzwerkstoff
8 x Stahl | OG1 | Stahl
2 x Platten | OG1 | Platten
2 x Luftschicht horizontal | OG1 | Luftschicht horizontal
3 x Sperrschicht | OG1 | Sperrschicht
2 x Stampfbeton | OG1 | Stampfbeton
Kies | OG1 | Kies
62 x Aluminium | OG1 | Aluminium
24 x Profilit | OG1 | Profilit
2 x Stehfalz | DG1 | Stehfalz
2 x Bauholz | DG1 | Bauholz
4 x Luftschicht horizontal | DG1 | Luftschicht horizontal
38 x EPS 1 | DG1 | EPS 1
63 x Gipskarton | DG1 | Gipskarton
34 x Mineralwolle weich | DG1 | Mineralwolle weich
14 x Stahlbeton Wand | DG1 | Stahlbeton Wand
34 x Zementputz | DG1 | Zementputz
2 x Gipsputz | DG1 | Gipsputz
10 x Fliesen | DG1 | Fliesen
15 x Estrich | DG1 | Estrich
15 x Trittschalldämmung | DG1 | Trittschalldämmung
15 x Schüttung | DG1 | Schüttung
5 x Parkett | DG1 | Parkett
105 x BEKLEIDUNG | DG1 | BEKLEIDUNG
3 x Stahlbeton Decke | DG1 | Stahlbeton Decke
34 x Vollholz | DG1 | Vollholz
17 x Brettschichtholz | DG1 | Brettschichtholz
17 x Stahl | DG1 | Stahl
17 x Holzwerkstoff | DG1 | Holzwerkstoff
15 x Stahlbeton | DG1 | Stahlbeton
Holzwolledämmplatte | DG1 | Holzwolledämmplatte
2 x Platten | DG1 | Platten
10 x Sperrschicht | DG1 | Sperrschicht
5 x XPS | DG1 | XPS
3 x Kies | DG1 | Kies
70 x Aluminium | DG1 | Aluminium
27 x Profilit | DG1 | Profilit
4 x Stehfalz | DG2 | Stehfalz
4 x Bauholz | DG2 | Bauholz
7 x Luftschicht horizontal | DG2 | Luftschicht horizontal
35 x EPS 1 | DG2 | EPS 1
47 x Zementputz | DG2 | Zementputz
23 x Stahlbeton Wand | DG2 | Stahlbeton Wand
264 x Blech | DG2 | Blech
31 x Gipskarton | DG2 | Gipskarton
21 x Mineralwolle weich | DG2 | Mineralwolle weich
7 x Stahl | DG2 | Stahl
7 x Holzwerkstoff | DG2 | Holzwerkstoff
14 x Vollholz | DG2 | Vollholz
7 x Stahlbeton | DG2 | Stahlbeton
7 x Brettschichtholz | DG2 | Brettschichtholz
3 x Parkett | DG2 | Parkett
8 x Estrich | DG2 | Estrich
8 x Trittschalldämmung | DG2 | Trittschalldämmung
8 x Schüttung | DG2 | Schüttung
5 x Fliesen | DG2 | Fliesen
26 x BEKLEIDUNG | DG2 | BEKLEIDUNG
3 x Platten | DG2 | Platten
6 x Sperrschicht | DG2 | Sperrschicht
3 x XPS | DG2 | XPS
75 x Aluminium | DG2 | Aluminium
29 x Profilit | DG2 | Profilit
Stehfalz | DA | Stehfalz
36 x Vollholz | DA | Vollholz
35 x EPS 1 | DA | EPS 1
18 x Brettschichtholz | DA | Brettschichtholz
17 x Stahlbeton Wand Garage | DA | Stahlbeton Wand Garage
18 x Holzwerkstoff | DA | Holzwerkstoff
18 x Stahl | DA | Stahl
17 x Zementputz | DA | Zementputz
3 x Kies | DA | Kies
6 x Folie | DA | Folie
3 x XPS | DA | XPS

# IfcColumn: Stahlbeton 300 x 300 (4)
Material: Stahlbeton
Pset_ColumnCommon - Brandwiderstand: R 90; FireRating: R 90; IsExternal: no; LoadBearing: yes; Status: Neu
Qto_ColumnBaseQuantities - CrossSectionArea: 0.09 m2; NetSurfaceArea: 0 m2
Name | In | Length (m) | OuterSurfaceArea (m2) | GrossSurfaceArea (m2) | GrossVolume (m3) = NetVolume (m3)
Stütze-002 | UG1 | 2.88 | 3.456 | 3.636 | 0.2592
Stütze-002 | EG | 2.76 | 3.312 | 3.492 | 0.2484
Stütze-002 | OG1 | 2.76 | 3.312 | 3.492 | 0.2484
Stütze-002 | DG1 | 2.76 | 3.312 | 3.492 | 0.2484

# IfcColumn: Stahlbeton Wand 250 (4)
In: UG1
Material: Stahlbeton Wand
Pset_ColumnCommon - Brandwiderstand: R 90; FireRating: R 90; IsExternal: no; LoadBearing: yes; Status: Neu
Qto_ColumnBaseQuantities - CrossSectionArea: 0.5375 m2
Name | Length (m) | OuterSurfaceArea (m2) | GrossSurfaceArea (m2) | GrossVolume (m3) = NetVolume (m3)
Wand-005 | 0.800458 | 4.9172 | 5.31743 | 0.430246
Wand-004 | 0.800458 | 4.9172 | 5.31743 | 0.430246
Wand-003 | 0.798804 | 4.90926 | 5.30866 | 0.429357
Wand-002 | 0.798804 | 4.90926 | 5.30866 | 0.429357

# IfcCovering: Balkon 220 (2)
In: OG1
Pset_CoveringCommon - FireRating: ND; IsExternal: yes; Status: Neu; SurfaceSpreadOfFlame: B; ThermalTransmittance: 1.5
Qto_CoveringBaseQuantities - Width: 0.22 m
Name | GrossArea (m2) | NetArea (m2)
Decke-005 | 17.3859 | 17.3454
Decke-005 | 8.04298 | 7.99156

# IfcCovering: Balkon Vordach 65, Decke-005
In: OG1
Pset_CoveringCommon - FireRating: ND; IsExternal: yes; Status: Neu; SurfaceSpreadOfFlame: A2; ThermalTransmittance: 0
Qto_CoveringBaseQuantities - Width: 0.065 m; GrossArea: 6.88621 m2; NetArea: 6.78004 m2

# IfcCovering: Balkon vor Terrasse 220 (5)
Pset_CoveringCommon - FireRating: ND; IsExternal: yes; Status: Neu; SurfaceSpreadOfFlame: B; ThermalTransmittance: 1.5
Qto_CoveringBaseQuantities - Width: 0.22 m
Name | In | GrossArea (m2) | NetArea (m2)
Decke-005 | DG1 | 30.3223 | 30.2396
Decke-005 | DG1 | 7.96672 | 7.93058
Decke-005 | DG2 | 6.19374 | 6.16054
Decke-005 | DG2 | 19.779 | 19.6989
Decke-005 | DG2 | 5.54484 | 5.48154

# IfcCovering: Balkon vor Terrasse Kies 220 (3)
In: DG1
Pset_CoveringCommon - FireRating: ND; IsExternal: yes; Status: Neu; SurfaceSpreadOfFlame: B; ThermalTransmittance: 1.5
Qto_CoveringBaseQuantities - Width: 0.22 m
Name | GrossArea (m2) | NetArea (m2)
Decke-005 | 4.08072 | 4.02891
Decke-005 | 4.68201 | 4.61872
Decke-005 | 3.57397 | 3.52202

# IfcCovering: DE 01 Decke Wohnung/Wohnung Fließen 220 (35)
Pset_CoveringCommon - FireRating: EI 60; IsExternal: no; Status: Neu; SurfaceSpreadOfFlame: A2; ThermalTransmittance: 0.24
Qto_CoveringBaseQuantities - Width: 0.22 m
Name | In | GrossArea (m2) | NetArea (m2)
Decke-001 | EG | 5.60864 | 5.60852
Decke-001 | EG | 8.7714 | 8.7714
Decke-001 | EG | 2.96895 | 2.96895
Decke-002 | EG | 10.9402 | 10.9402
Decke-003 | EG | 6.19516 | 6.19331
Decke-003 | EG | 2.76099 | 2.76099
Decke-004 | EG | 1.82724 | 1.82724
Decke-003 | EG | 3.60457 | 3.60455
Decke-004 | EG | 5.01068 | 5.01068
Decke-001 | EG | 8.57542 | 8.57534
Decke-001 | OG1 | 7.33091 | 7.33079
Decke-001 | OG1 | 8.7714 | 8.7714
Decke-001 | OG1 | 2.96895 | 2.96895
Decke-002 | OG1 | 10.9402 | 10.9402
Decke-003 | OG1 | 6.19516 | 6.19516
Decke-003 | OG1 | 2.76099 | 2.76099
Decke-004 | OG1 | 1.82724 | 1.82724
Decke-003 | OG1 | 3.60457 | 3.60455
Decke-004 | OG1 | 7.12706 | 7.12703
Decke-001 | OG1 | 8.53575 | 8.53567
Decke-004 | DG1 | 5.01068 | 5.01068
Decke-001 | DG1 | 5.60864 | 5.60852
Decke-001 | DG1 | 8.54044 | 8.53976
Decke-001 | DG1 | 8.77135 | 8.70745
Decke-001 | DG1 | 2.96895 | 2.96496
Decke-002 | DG1 | 10.9533 | 10.8521
Decke-003 | DG1 | 6.19516 | 6.19417
Decke-003 | DG1 | 2.76099 | 2.76099
Decke-004 | DG1 | 1.82724 | 1.82724
Decke-003 | DG1 | 3.60457 | 3.60455
Decke-004 | DG2 | 12.6036 | 12.603
Decke-004 | DG2 | 15.2291 | 13.366
Decke-004 | DG2 | 1.89067 | 1.89067
Decke-004 | DG2 | 6.66451 | 6.52707
Decke-004 | DG2 | 6.50705 | 5.57217

# IfcCovering: DE 01 Decke Wohnung/Wohnung Parkett 220 (20)
Pset_CoveringCommon - FireRating: EI 60; IsExternal: no; Status: Neu; SurfaceSpreadOfFlame: A2; ThermalTransmittance: 0.24
Qto_CoveringBaseQuantities - Width: 0.22 m
Name | In | GrossArea (m2) | NetArea (m2)
Decke-005 | EG | 34.2292 | 34.2292
Decke-005 | EG | 14.5779 | 14.5779
Decke-006 | EG | 13.4653 | 13.4653
Decke-007 | EG | 13.4869 | 13.4869
Decke-008 | EG | 34.6471 | 34.6471
Decke-009 | EG | 15.6508 | 15.6508
Decke-005 | OG1 | 34.2292 | 34.2292
Decke-005 | OG1 | 18.5005 | 18.5005
Decke-006 | OG1 | 13.4653 | 13.4653
Decke-007 | OG1 | 13.4869 | 13.4869
Decke-008 | OG1 | 42.4805 | 42.4805
Decke-009 | OG1 | 20.0078 | 20.0078
Decke-005 | DG1 | 34.2292 | 33.4395
Decke-005 | DG1 | 14.5779 | 13.8868
Decke-006 | DG1 | 15.5011 | 14.9123
Decke-008 | DG1 | 35.0155 | 35.0155
Decke-009 | DG1 | 15.6508 | 15.6508
Decke-008 | DG2 | 42.0557 | 42.0555
Decke-009 | DG2 | 18.1797 | 17.1062
Decke-009 | DG2 | 19.2049 | 19.2049

# IfcCovering: Platten 210 (3)
In: EG
Material: Platten
Pset_CoveringCommon - FireRating: ND; IsExternal: yes; Status: Neu; SurfaceSpreadOfFlame: A2; ThermalTransmittance: 1
Qto_CoveringBaseQuantities - Width: 0.21 m; Platten, Width: 0.21 m
Name | GrossArea (m2) | NetArea (m2)
Decke-005 | 52.676 | 52.676
Decke-005 | 17.2312 | 17.2306
Decke-005 | 7.99865 | 7.99865

# IfcCovering: Vorsatzschale Garage 130 (7)
In: UG1
Pset_CoveringCommon - FireRating: EI 90; IsExternal: no; Status: Neu; SurfaceSpreadOfFlame: A2; ThermalTransmittance: 0.3
Qto_CoveringBaseQuantities - Width: 0.13 m
Name | GrossArea (m2) | NetArea (m2)
Decke-005 | 34.662 | 34.662
Decke-006 | 32.6363 | 32.6176
Decke-005 | 49.469 | 49.469
Decke-005 | 27.2848 | 27.2843
Decke-005 | 8.22765 | 8.22765
Decke-006 | 4.77207 | 4.77207
Decke-007 | 23.1117 | 23.0212

# IfcCurtainWall: Fassadentyp (3)
In: DG2
Pset_CurtainWallCommon - FireRating: R 90; IsExternal: yes; Status: Neu; SurfaceSpreadOfFlame: ND; ThermalTransmittance: 0
Qto_CurtainWallQuantities - Width: 0.168 m
Name | Length (m) | Height (m) | GrossSideArea (m2) = NetSideArea (m2)
Fassade-001 | 1.53024 | 2.8 | 4.28468
Fassade-001 | 4.88701 | 4.35 | 21.2585
Fassade-001 | 8.01195 | 4.35 | 34.852

# IfcDoor: Blockfutter 26 (14)
Type - OperationType: SINGLE_SWING_LEFT
OverallHeight: 2.265 m
Pset_DoorCommon - FireRating: ND; HandicapAccessible: no; IsExternal: no; SelfClosing: no; SmokeStop: no; Status: Neu; ThermalTransmittance: 2.2
Qto_DoorBaseQuantities - Height: 2.265 m
Name | In | OverallWidth (m) = Width (m) | FireExit | IDDoor | IDNextDoor | Perimeter (m) | Area (m2)
Tür-016 | EG | 0.89 | no | E0-16 | E0-13 | 6.31 | 2.01585
Tür-016 | EG | 0.89 | no | E0-10 | E0-08 | 6.31 | 2.01585
Tür-016 | EG | 0.89 | no | E0-11 | E0-08 | 6.31 | 2.01585
Tür-016 | EG | 0.89 | no | E0-17 | E0-13 | 6.31 | 2.01585
Tür-017 | EG | 0.99 | yes | E0-13 | E0-12 | 6.51 | 2.24235
Tür-016 | OG1 | 0.89 | no | E1-16 | E1-13 | 6.31 | 2.01585
Tür-016 | OG1 | 0.89 | no | E1-10 | E1-08 | 6.31 | 2.01585
Tür-016 | OG1 | 0.89 | no | E1-11 | E1-08 | 6.31 | 2.01585
Tür-016 | OG1 | 0.89 | no | E1-17 | E1-13 | 6.31 | 2.01585
Tür-017 | OG1 | 0.99 | yes | E1-13 | E1-12 | 6.51 | 2.24235
Tür-016 | DG1 | 0.89 | no | E2-15 | E2-12 | 6.31 | 2.01585
Tür-016 | DG1 | 0.89 | no | E2-10 | E2-08 | 6.31 | 2.01585
Tür-016 | DG1 | 0.89 | no | E2-16 | E2-12 | 6.31 | 2.01585
Tür-017 | DG1 | 0.99 | yes | E2-12 | E2-11 | 6.51 | 2.24235

# IfcDoor: Blockfutter 26 (27)
Type - OperationType: SINGLE_SWING_RIGHT
OverallHeight: 2.265 m
Pset_DoorCommon - FireRating: ND; HandicapAccessible: no; IsExternal: no; SelfClosing: no; SmokeStop: no; Status: Neu; ThermalTransmittance: 2.2
Qto_DoorBaseQuantities - Height: 2.265 m
Name | In | OverallWidth (m) = Width (m) | FireExit | IDDoor | IDNextDoor | Perimeter (m) | Area (m2)
Tür-016 | EG | 0.89 | no | E0-09 | E0-08 | 6.31 | 2.01585
Tür-016 | EG | 0.89 | no | E0-14 | E0-13 | 6.31 | 2.01585
Tür-016 | EG | 0.89 | no | E0-15 | E0-13 | 6.31 | 2.01585
Tür-017 | EG | 0.99 | yes | E0-12 | E0-08 | 6.51 | 2.24235
Tür-014 | EG | 0.89 | no | E0-05 | E0-03 | 6.31 | 2.01585
Tür-016 | EG | 0.89 | no | E0-04 | E0-03 | 6.31 | 2.01585
Tür-015 | EG | 0.89 | no | E0-06 | E0-03 | 6.31 | 2.01585
Tür-015 | OG1 | 0.89 | no | E1-06 | E1-03 | 6.31 | 2.01585
Tür-014 | OG1 | 0.89 | no | E1-05 | E1-03 | 6.31 | 2.01585
Tür-016 | OG1 | 0.89 | no | E1-04 | E1-03 | 6.31 | 2.01585
Tür-016 | OG1 | 0.89 | no | E1-09 | E1-08 | 6.31 | 2.01585
Tür-016 | OG1 | 0.89 | no | E1-14 | E1-13 | 6.31 | 2.01585
Tür-016 | OG1 | 0.89 | no | E1-15 | E1-13 | 6.31 | 2.01585
Tür-017 | OG1 | 0.99 | yes | E1-12 | E1-08 | 6.51 | 2.24235
Tür-015 | DG1 | 0.89 | no | E2-06 | E2-03 | 6.31 | 2.01585
Tür-014 | DG1 | 0.89 | no | E2-05 | E2-03 | 6.31 | 2.01585
Tür-016 | DG1 | 0.89 | no | E2-04 | E2-03 | 6.31 | 2.01585
Tür-016 | DG1 | 0.89 | no | E2-09 | E2-08 | 6.31 | 2.01585
Tür-016 | DG1 | 0.89 | no | E2-13 | E2-12 | 6.31 | 2.01585
Tür-016 | DG1 | 0.89 | no | E2-14 | E2-12 | 6.31 | 2.01585
Tür-017 | DG1 | 0.99 | yes | E2-11 | E2-08 | 6.51 | 2.24235
Tür-018 | DG2 | 0.89 | no | E3-02 | E3-01 | 6.31 | 2.01585
Tür-020 | DG2 | 0.89 | no | E3-05 | E3-01 | 6.31 | 2.01585
Tür-019 | DG2 | 0.89 | no | E3-06 | E3-01 | 6.31 | 2.01585
Tür-016 | DG2 | 0.89 | no | E3-04 | E3-01 | 6.31 | 2.01585
Tür-017 | DG2 | 0.89 | no | E3-03 | E3-01 | 6.31 | 2.01585
Tür-021 | DG2 | 0.89 | no | E3-07 | E3-01 | 6.31 | 2.01585

# IfcDoor: Blockrahmentür 1-Fl 26 (9)
Type - OperationType: SINGLE_SWING_LEFT
OverallWidth: 1.1 m
Pset_DoorCommon - FireRating: EI2 30-C-Sm; IsExternal: no; Status: Neu; ThermalTransmittance: 2.2
Qto_DoorBaseQuantities - Width: 1.1 m
Name | In | OverallHeight (m) = Height (m) | FireExit | HandicapAccessible | SelfClosing = SmokeStop | IDDoor | IDNextDoor | Perimeter (m) | Area (m2)
Tür-001 | UG1 | 2.1 | no | no | yes | U1-03 | E0-01 | 6.4 | 2.31
Tür-001 | UG1 | 2.1 | no | no | yes | U1-04 | E0-01 | 6.4 | 2.31
Tür-002 | UG1 | 2.1 | no | no | yes | U1-07 | U1-06 | 6.4 | 2.31
Tür-001 | UG1 | 2.1 | yes | no | yes | U1-02 | E0-01 | 6.4 | 2.31
Tür-001 | UG1 | 2.1 | no | no | yes | U1-06 | E0-01 | 6.4 | 2.31
Tür-001 | EG | 2.32 | yes | yes | no | E0-08 | E0-01 | 6.84 | 2.552 | ZDB_DoorData - OccupancyNumberFlat: 4
Tür-001 | OG1 | 2.32 | yes | yes | no | E1-08 | E0-01 | 6.84 | 2.552 | ZDB_DoorData - OccupancyNumberFlat: 4
Tür-001 | DG1 | 2.32 | yes | yes | no | E2-08 | E0-01 | 6.84 | 2.552 | ZDB_DoorData - OccupancyNumberFlat: 3
Tür-001 | DG2 | 2.32 | yes | yes | no | E3-01 | E0-01 | 6.84 | 2.552 | ZDB_DoorData - OccupancyNumberFlat: 3

# IfcDoor: Blockrahmentür 1-Fl 26 (3)
Type - OperationType: SINGLE_SWING_RIGHT
OverallHeight: 2.32 m; OverallWidth: 1.1 m
Pset_DoorCommon - FireExit: yes; FireRating: EI2 30-C-Sm; HandicapAccessible: yes; IsExternal: no; SelfClosing: no; SmokeStop: no; Status: Neu; ThermalTransmittance: 2.2
ZDB_DoorData - IDNextDoor: E0-01; OccupancyNumberFlat: 2
Qto_DoorBaseQuantities - Height: 2.32 m; Width: 1.1 m; Perimeter: 6.84 m; Area: 2.552 m2
Name | In | IDDoor
Tür-001 | EG | E0-03
Tür-001 | OG1 | E1-03
Tür-001 | DG1 | E2-03

# IfcDoor: Eingang 01 1-Fl 26, Tür-001
In: EG
Type - OperationType: SINGLE_SWING_LEFT
OverallHeight: 2.46 m; OverallWidth: 1.25 m
Pset_DoorCommon - FireExit: yes; FireRating: EI2 30-C; HandicapAccessible: yes; IsExternal: yes; SelfClosing: yes; SmokeStop: no; Status: Neu; ThermalTransmittance: 2.1
ZDB_DoorData - IDDoor: E0-01; IDNextDoor: LastDoor
Qto_DoorBaseQuantities - Height: 2.46 m; Width: 1.25 m; Perimeter: 7.42 m; Area: 3.075 m2

# IfcDoor: Ladentür 1-Fl 26, Tür-001
In: EG
Type - OperationType: SINGLE_SWING_RIGHT
OverallHeight: 2.26 m; OverallWidth: 4.441 m
Pset_DoorCommon - FireExit: no; FireRating: ND; HandicapAccessible: no; IsExternal: yes; SelfClosing: no; SmokeStop: no; Status: Neu; ThermalTransmittance: 0
ZDB_DoorData - IDDoor: E0-27; IDNextDoor: ND
Qto_DoorBaseQuantities - Height: 2.04 m; Width: 4.441 m; Perimeter: 12.962 m; Area: 9.05964 m2

# IfcDoor: Schiebetür 02 1-Fl 26 (3)
Type - OperationType: SLIDING_TO_RIGHT
OverallHeight: 2.25 m; OverallWidth: 0.96 m
Pset_DoorCommon - FireExit: no; FireRating: ND; HandicapAccessible: no; IsExternal: no; SelfClosing: no; SmokeStop: no; Status: Neu; ThermalTransmittance: 2.5
Qto_DoorBaseQuantities - Height: 2.25 m; Width: 0.96 m; Perimeter: 6.42 m; Area: 2.16 m2
Name | In | IDDoor | IDNextDoor
Tür-001 | EG | E0-07 | E0-03
Tür-001 | OG1 | E1-07 | E1-03
Tür-001 | DG1 | E2-07 | E2-03

# IfcDoor: Sektionaltor 26, Tür-001
In: UG1
Type - OperationType: USERDEFINED
OverallHeight: 3.08 m; OverallWidth: 3.36 m
Pset_DoorCommon - FireExit: no; FireRating: ND; HandicapAccessible: no; IsExternal: yes; SelfClosing: yes; SmokeStop: no; Status: Neu; ThermalTransmittance: 0
ZDB_DoorData - IDDoor: U1-01; IDNextDoor: U1-02
Qto_DoorBaseQuantities - Height: 2.23 m; Width: 3.36 m; Perimeter: 11.18 m; Area: 7.4928 m2

# IfcDoor: Teleskoptür 26 (5)
Type - OperationType: DOUBLE_DOOR_SLIDING
OverallWidth: 1.16 m
Pset_DoorCommon - FireExit: no; FireRating: ND; HandicapAccessible: yes; IsExternal: no; SelfClosing: no; SmokeStop: no; Status: Neu; ThermalTransmittance: 2.2
ZDB_DoorData - IDNextDoor: E0-01
Qto_DoorBaseQuantities - Width: 1.16 m
Name | In | OverallHeight (m) | IDDoor | Height (m) | Perimeter (m) | Area (m2)
Tür-003 | UG1 | 2.35 | U1-05 | 2.35 | 7.02 | 2.726
Tür-003 | EG | 2.57 | E0-02 | 2.57 | 7.46 | 2.9812
Tür-003 | OG1 | 2.57 | E1-02 | 2.57 | 7.46 | 2.9812
Tür-003 | DG1 | 2.57 | E2-02 | 2.57 | 7.46 | 2.9812
Tür-003 | DG2 | 2.57 | E3-11 | 2.49 | 7.3 | 2.8884

# IfcDoor: Terrassentür 1-Fl 26, Tür-001
In: EG
Type - OperationType: SINGLE_SWING_LEFT
OverallHeight: 2.58 m; OverallWidth: 1.1 m
Pset_DoorCommon - FireExit: yes; FireRating: EI 30; HandicapAccessible: no; IsExternal: yes; SelfClosing: no; SmokeStop: no; Status: Neu; ThermalTransmittance: 0.6
ZDB_DoorData - MainWindow: yes; IDDoor: E0-19; IDNextDoor: ND
Qto_DoorBaseQuantities - Height: 2.58 m; Width: 1.1 m; Perimeter: 7.36 m; Area: 2.838 m2

# IfcDoor: Terrassentür 1-Fl 26, Tür-001
In: EG
Type - OperationType: SINGLE_SWING_RIGHT
OverallHeight: 2.58 m; OverallWidth: 1.1 m
Pset_DoorCommon - FireExit: yes; FireRating: EI 30; HandicapAccessible: no; IsExternal: yes; SelfClosing: no; SmokeStop: no; Status: Neu; ThermalTransmittance: 0.6
ZDB_DoorData - MainWindow: yes; IDDoor: E0-20; IDNextDoor: ND
Qto_DoorBaseQuantities - Height: 2.58 m; Width: 1.1 m; Perimeter: 7.36 m; Area: 2.838 m2

# IfcDoor: Terrassentür 2-Fl 26 (8)
Type - OperationType: DOUBLE_DOOR_SINGLE_SWING
OverallHeight: 2.58 m; OverallWidth: 2 m
Pset_DoorCommon - FireExit: yes; FireRating: EI 30; HandicapAccessible: no; IsExternal: yes; SelfClosing: no; SmokeStop: no; Status: Neu; ThermalTransmittance: 0.6
ZDB_DoorData - MainWindow: yes; IDNextDoor: ND
Qto_DoorBaseQuantities - Height: 2.58 m; Width: 2 m; Perimeter: 9.16 m; Area: 5.16 m2
Name | In | IDDoor
Tür-002 | EG | E0-21
Tür-002 | EG | E0-18
Tür-002 | EG | E0-23
Tür-002 | EG | E0-24
Tür-002 | EG | E0-26
Tür-002 | OG1 | E1-19
Tür-002 | DG2 | E3-10
Tür-002 | DG2 | E3-08

# IfcDoor: Terrassentür 2-Fl KS 26 (7)
Type - OperationType: DOUBLE_DOOR_SINGLE_SWING
OverallHeight: 2.58 m
Pset_DoorCommon - FireExit: yes; FireRating: EI 30; HandicapAccessible: no; IsExternal: yes; SelfClosing: no; SmokeStop: no; Status: Neu; ThermalTransmittance: 0.6
ZDB_DoorData - MainWindow: yes; IDNextDoor: ND
Qto_DoorBaseQuantities - Height: 2.58 m
Name | In | OverallWidth (m) = Width (m) | IDDoor | Perimeter (m) | Area (m2)
Tür-001 | EG | 3.63198 | E0-22 | 12.424 | 9.3705
Tür-001 | EG | 3.28169 | E0-25 | 11.7234 | 8.46676
Tür-001 | OG1 | 3.22 | E1-20 | 11.6 | 8.3076
Tür-001 | OG1 | 3.63198 | E1-18 | 12.424 | 9.3705
Tür-001 | DG1 | 3.22 | E2-18 | 11.6 | 8.3076
Tür-001 | DG1 | 3.63198 | E2-17 | 12.424 | 9.3705
Tür-001 | DG2 | 3.63198 | E3-09 | 12.424 | 9.3705

# IfcFurniture: Briefkastenanlage 26, Objekt-0002
In: EG
Pset_FurnitureTypeCommon - IsBuiltIn: no; Status: Neu

# IfcFurniture: Großmüllcontainer 26, Objekt-0011
In: EG
Pset_FurnitureTypeCommon - IsBuiltIn: no; Status: Neu

# IfcFurniture: Großmülltonne 26 (3)
In: EG
Pset_FurnitureTypeCommon - IsBuiltIn: no; Status: Neu
Name
Objekt-0009
Objekt-0010
Objekt-0011

# IfcFurniture: Konzeptküche 26 (14)
Pset_FurnitureTypeCommon - IsBuiltIn: no; Status: Neu
Name | In
4 x Objekt-0002 | EG
4 x Objekt-0002 | OG1
4 x Objekt-0002 | DG1
2 x Objekt-0002 | DG2

# IfcFurniture: Seitenwand-Gitter 26 (2)
Pset_FurnitureTypeCommon - IsBuiltIn: yes; Status: Neu
Name | In
Objekt-0002 | UG1
Objekt-0002 | EG

# IfcOpeningElement (117)
Name | In | Depth (m) | Height (m) | Width (m) | Area (m2) | Volume (m3)
3 x Tür-001 | UG1 | 0.2 | 2.1 | 1.1 | 2.31 | 0.110225
Tür-003 | UG1 | 0.2 | 2.35 | 1.16 | 2.726 | 0.157066
Tür-002 | UG1 | 0.2 | 2.1 | 1.1 | 2.31 | 0.110225
Tür-001 | UG1 | 0.265 | 2.1 | 1.1 | 2.31 | 0.110225
Tür-001 | UG1 | 0.2 | 2.23 | 3.36 | 7.4928 | 0.433423
8 x Tür-016 | EG | 0.105 | 2.265 | 0.89 | 2.01585 | 0.0878785
Tür-017 | EG | 0.105 | 2.265 | 0.99 | 2.24235 | 0.096366
Tür-003 | EG | 0.2 | 2.57 | 1.16 | 2.9812 | 0.157066
2 x Tür-001 | EG | 0.265 | 2.32 | 1.1 | 2.552 | 0.1103
Tür-017 | EG | 0.2 | 2.265 | 0.99 | 2.24235 | 0.117698
5 x Tür-002 | EG | 0.42 | 2.58 | 2 | 5.16 | 0.219293
2 x Tür-001 | EG | 0.42 | 2.58 | 1.1 | 2.838 | 0.133281
Tür-001 | EG | 0.42 | 2.58 | 3.63198 | 9.3705 | 0.358699
Tür-001 | EG | 0.42 | 2.58 | 3.28169 | 8.46676 | 0.328851
Fenster-001 | EG | 0.42 | 1.5 | 1.9 | 2.85 | 0.123335
Fenster-001 | EG | 0.42 | 1.5 | 0.7 | 1.05 | 0.045208
Tür-001 | EG | 0.42 | 2.46 | 1.25 | 3.075 | 0.140786
Tür-001 | EG | 0.105 | 2.25 | 0.96 | 2.16 | 0.0361734
Tür-014 | EG | 0.105 | 2.265 | 0.89 | 2.01585 | 0.0878785
Tür-015 | EG | 0.105 | 2.265 | 0.89 | 2.01585 | 0.0878785
Tür-001 | EG | 0.08 | 2.04 | 4.441 | 9.05964 | 0.136315
Tür-015 | OG1 | 0.105 | 2.265 | 0.89 | 2.01585 | 0.0878785
Tür-014 | OG1 | 0.105 | 2.265 | 0.89 | 2.01585 | 0.0878785
8 x Tür-016 | OG1 | 0.105 | 2.265 | 0.89 | 2.01585 | 0.0878785
Tür-001 | OG1 | 0.105 | 2.25 | 0.96 | 2.16 | 0.0361734
5 x Fenster-001 | OG1 | 0.42 | 2.26 | 1.8 | 4.068 | 0.142877
Fenster-001 | OG1 | 0.42 | 2.26 | 1.05 | 2.373 | 0.0875798
Tür-001 | OG1 | 0.42 | 2.58 | 3.22 | 8.3076 | 0.255949
Tür-017 | OG1 | 0.105 | 2.265 | 0.99 | 2.24235 | 0.096366
2 x Tür-001 | OG1 | 0.265 | 2.32 | 1.1 | 2.552 | 0.1103
Tür-003 | OG1 | 0.2 | 2.57 | 1.16 | 2.9812 | 0.157066
Tür-017 | OG1 | 0.2 | 2.265 | 0.99 | 2.24235 | 0.117698
3 x Fenster-001 | OG1 | 0.42 | 2.26 | 0.9 | 2.034 | 0.0792584
2 x Fenster-001 | OG1 | 0.42 | 2.26 | 0.65 | 1.469 | 0.0653894
Tür-002 | OG1 | 0.42 | 2.58 | 2 | 5.16 | 0.150893
Tür-001 | OG1 | 0.42 | 2.58 | 3.63198 | 9.3705 | 0.281918
DFenst-002 | DG1 |  | 1.4 | 1.14476 | 1.60266 | 0.336558
DFenst-002 | DG1 |  | 1.4 | 1.14 | 1.596 | 0.33516
2 x DFenst-002 | DG1 |  | 1.6 | 1 | 1.6 | 0.336
Fenster-001 | DG1 | 0.42 | 2.26 | 1.05 | 2.373 | 0.0875798
2 x Fenster-001 | DG1 | 0.42 | 2.26 | 0.65 | 1.469 | 0.0653894
Tür-001 | DG1 | 0.42 | 2.58 | 3.22 | 8.3076 | 0.255949
Tür-015 | DG1 | 0.105 | 2.265 | 0.89 | 2.01585 | 0.0878785
Tür-014 | DG1 | 0.105 | 2.265 | 0.89 | 2.01585 | 0.0878785
7 x Tür-016 | DG1 | 0.105 | 2.265 | 0.89 | 2.01585 | 0.0878785
Tür-001 | DG1 | 0.105 | 2.25 | 0.96 | 2.16 | 0.0361734
2 x Tür-001 | DG1 | 0.265 | 2.32 | 1.1 | 2.552 | 0.1103
Tür-017 | DG1 | 0.105 | 2.265 | 0.99 | 2.24235 | 0.096366
Tür-017 | DG1 | 0.2 | 2.265 | 0.99 | 2.24235 | 0.117698
3 x Fenster-001 | DG1 | 0.42 | 2.26 | 0.9 | 2.034 | 0.0792584
3 x Fenster-001 | DG1 | 0.42 | 2.26 | 1.8 | 4.068 | 0.142877
Tür-001 | DG1 | 0.42 | 2.58 | 3.63198 | 9.3705 | 0.281918
Tür-003 | DG1 | 0.2 | 2.57 | 1.16 | 2.9812 | 0.157066
Tür-003 | DG2 | 0.2 | 2.49 | 1.16 | 2.8884 | 0.157066
Fenster-001 | DG2 | 0.42 | 2 | 1.05 | 2.1 | 0.0801178
Tür-001 | DG2 | 0.265 | 2.32 | 1.1 | 2.552 | 0.1103
Tür-018 | DG2 | 0.2 | 2.265 | 0.89 | 2.01585 | 0.108783
Fenster-001 | DG2 | 0.42 | 2.26 | 1.8 | 4.068 | 0.142877
2 x Fenster-001 | DG2 | 0.42 | 2.26 | 0.9 | 2.034 | 0.0792584
Tür-001 | DG2 | 0.42 | 2.58 | 3.63198 | 9.3705 | 0.281918
2 x Tür-002 | DG2 | 0.42 | 2.58 | 2 | 5.16 | 0.219293
Tür-020 | DG2 | 0.105 | 2.265 | 0.89 | 2.01585 | 0.0878785
Tür-019 | DG2 | 0.105 | 2.265 | 0.89 | 2.01585 | 0.0878785
Tür-016 | DG2 | 0.105 | 2.265 | 0.89 | 2.01585 | 0.0878785
Tür-017 | DG2 | 0.105 | 2.265 | 0.89 | 2.01585 | 0.0878785
Tür-021 | DG2 | 0.105 | 2.265 | 0.89 | 2.01585 | 0.0878785
2 x DFenst-002 | DG2 |  | 1.4 | 1.14 | 1.596 | 0.33516
2 x DFenst-002 | DG2 |  | 1.6 | 1 | 1.6 | 0.336
DFenst-002 | DA |  | 1.09985 | 1.09817 | 1.20783 | 0.434819
DFenst-002 | DA |  | 1.09985 | 1.09817 | 1.20783 | 0.35027

# IfcPlate: Blech 20 (2)
In: DA
Material: Blech
Pset_PlateCommon - FireRating: R 90; IsExternal: yes; LoadBearing: no; Status: Neu; ThermalTransmittance: 0.04
Qto_PlateBaseQuantities - Width: 0.02 m
Name | Perimeter (m) | GrossArea (m2) = NetArea (m2) | GrossVolume (m3) = NetVolume (m3)
Dach-002 | 3.97571 | 0.689294 | 0.0137859
Dach-003 | 2.67309 | 0.437454 | 0.00874907

# IfcRailing: Geländerart (25)
Name | In | Diameter (m) | Height (m) | IsExternal | Status | Length (m)
Geländer - 001 | UG1 | 0.025 | 90 | no | Neu | 5.47802
Geländer - 001 | UG1 | 0.025 | 90 | no | Neu | 2.43619
Geländer - 001 | UG1 | 0.025 | 90 | no | Neu | 2.87268
Geländer - 001 | EG | 0.025 | 90 | no | Neu | 5.40886
Geländer - 002 | EG | 0.025 | 90 | no | Neu | 2.36441
Geländer - 001 | EG | 0.025 | 90 | no | Neu | 2.8751
Geländer - 001 | EG |  |  |  | EXISTING | 82.9681
Geländer - 001 | EG |  |  |  | EXISTING | 16.5088
Geländer - 001 | EG |  |  |  | EXISTING | 16.5672
Geländer - 001 | EG |  |  |  | EXISTING | 8.31531
Geländer - 001 | EG |  |  |  | EXISTING | 0.428802
Geländer - 001 | OG1 | 0.025 | 90 | no | Neu | 5.40886
Geländer - 002 | OG1 | 0.025 | 90 | no | Neu | 2.36441
Geländer - 001 | OG1 | 0.025 | 90 | no | Neu | 2.8751
Geländer - 001 | OG1 | 0.03 | 100 | yes | Neu | 12.9257
Geländer - 001 | OG1 | 0.03 | 100 | yes | Neu | 7.54172
Geländer - 001 | DG1 | 0.025 | 90 | no | Neu | 5.40886
Geländer - 002 | DG1 | 0.025 | 90 | no | Neu | 2.36441
Geländer - 001 | DG1 | 0.025 | 90 | no | Neu | 2.8751
Geländer - 001 | DG1 | 0.03 | 100 | yes | Neu | 14.8604
Geländer - 001 | DG1 | 0.03 | 100 | yes | Neu | 8.6294
Geländer - 001 | DG2 | 0.025 | 90 | no | Neu | 1.60346
Geländer - 001 | DG2 | 0.03 | 100 | yes | Neu | 7.68729
Geländer - 001 | DG2 | 0.03 | 100 | yes | Neu | 9.95337
Geländer - 001 | DG2 | 0.03 | 100 | yes | Neu | 6.31974

# IfcRamp: Rampe Neu 450 (2)
In: UG1
Pset_RampCommon - FireExit: no; FireRating: ND; HandicapAccessible: no; IsExternal: yes; LoadBearing: yes; RequiredHeadroom: 2.1 m; Status: Neu; ThermalTransmittance: 0.434
Name | RequiredSlope (deg)
Dach-001 | 1031.32
Dach-001 | 286.479

# IfcRoof: Flachdach Kies Dachaufbau 360 (2)
In: DA
Pset_RoofCommon - FireRating: ND; IsExternal: yes; LoadBearing: no; Status: Neu; ThermalTransmittance: 0.17
ZDB_RoofData - RoofSlope: 0
Name | GrossArea (m2) | NetArea (m2)
Dach-002 | 2.63313 | 2.63313
Dach-002 | 77.8785 | 75.5439

# IfcRoof: Flachdach Kies Dachaufbau Treppenbereich 290, Dach-002
In: DA
Pset_RoofCommon - FireRating: ND; IsExternal: yes; LoadBearing: no; Status: Neu; ThermalTransmittance: 0.17
ZDB_RoofData - RoofSlope: 0
Qto_RoofBaseQuantities - GrossArea: 23.4004 m2; NetArea: 22.1925 m2

# IfcRoof: Schrägdach Dachaufbau 210 (6)
Pset_RoofCommon - FireRating: ND; IsExternal: yes; LoadBearing: no; Status: Neu; ThermalTransmittance: 0.13
Name | In | RoofSlope | GrossArea (m2) | NetArea (m2)
Dach-001 | DG1 | 1.0472 | 11.3284 | 8.12979
Dach-001 | DG1 | 0 | 12.2142 | 9.01422
Dach-001 | DG2 | 0 | 5.00804 | 5.00804
Dach-001 | DG2 | 0 | 3.0499 | 3.0499
Dach-001 | DG2 | 0 | 20.2075 | 17.0155
Dach-001 | DG2 | 0 | 18.3646 | 15.1646

# IfcRoof: Stahlbeton Dach 200 (5)
Material: Stahlbeton Dach
Pset_RoofCommon - FireRating: REI 90; IsExternal: yes; LoadBearing: yes; Status: Neu; ThermalTransmittance: 2.84
Name | In | RoofSlope | GrossArea (m2) | NetArea (m2)
Dach-001 | DG1 | 1.0472 | 13.9941 | 9.823
Dach-001 | DG2 | 0.785398 | 19.6652 | 15.6775
Dach-001 | DG2 | 0 | 5.18388 | 5.18388
Dach-001 | DG2 | 0 | 4.95936 | 4.95936
Dach-002 | DA | 0 | 4.10159 | 4.10159

# IfcRoof: Stahlbeton Decke 200 (4)
Material: Stahlbeton Decke
Pset_RoofCommon - FireRating: REI 90; IsExternal: yes; LoadBearing: yes; Status: Neu; ThermalTransmittance: 2.84
Name | In | RoofSlope | GrossArea (m2) | NetArea (m2)
Dach-001 | DG1 | 0 | 13.068 | 8.78499
Dach-001 | DG2 | 0.785398 | 21.3669 | 17.2721
Dach-002 | DA | 0 | 24.3639 | 23.156
Dach-002 | DA | 0 | 87.7768 | 86.1249

# IfcSanitaryTerminal: Badewanne 26 (4)
Pset_SanitaryTerminalTypeCommon - Status: Neu
Name | In
Objekt-0009 | EG
Objekt-0009 | OG1
Objekt-0009 | DG1
Objekt-0009 | DG2

# IfcSanitaryTerminal: Duschwanne 26 (7)
Pset_SanitaryTerminalTypeCommon - Status: Neu
Name | In
2 x Objekt-0009 | EG
2 x Objekt-0009 | OG1
2 x Objekt-0009 | DG1
Objekt-0009 | DG2

# IfcSanitaryTerminal: WC 26 (10)
Pset_SanitaryTerminalTypeCommon - Status: Neu
Name | In
3 x Objekt-0009 | EG
3 x Objekt-0009 | OG1
3 x Objekt-0009 | DG1
Objekt-0009 | DG2

# IfcSanitaryTerminal: Waschbecken 01 26 (4)
Pset_SanitaryTerminalTypeCommon - Status: Neu
Name | In
Objekt-0009 | EG
Objekt-0009 | OG1
Objekt-0009 | DG1
Objekt-0009 | DG2

# IfcSanitaryTerminal: Waschbecken mehrfach 26 (10)
Pset_SanitaryTerminalTypeCommon - Status: Neu
Name | In
3 x Objekt-0009 | EG
3 x Objekt-0009 | OG1
3 x Objekt-0009 | DG1
Objekt-0009 | DG2

# IfcSanitaryTerminal: Waschmaschine 01 26 (5)
Pset_SanitaryTerminalTypeCommon - Status: Neu
Name | In
Objekt-0002 | EG
2 x Objekt-0002 | OG1
2 x Objekt-0002 | DG1

# IfcSlab: EB 01 Bodenplatte Garage 520, Decke-005
In: UG1
Pset_SlabCommon - Compartmentation: yes; FireRating: ND; IsExternal: yes; LoadBearing: yes; Status: Neu; ThermalTransmittance: 2.76
Qto_SlabBaseQuantities - Width: 0.52 m; Perimeter: 94.8052 m; GrossArea: 344.103 m2; NetArea: 344.103 m2; GrossVolume: 178.934 m3; NetVolume: 178.934 m3

# IfcSlab: EB 01 Bodenplatte Liftschacht 435, Decke-005
In: UG2
Pset_SlabCommon - Compartmentation: yes; FireRating: ND; IsExternal: yes; LoadBearing: yes; Status: Neu; ThermalTransmittance: 2.76
Qto_SlabBaseQuantities - Width: 0.435 m; Perimeter: 8.20194 m; GrossArea: 4.20449 m2; NetArea: 4.20449 m2; GrossVolume: 1.82895 m3; NetVolume: 1.82895 m3

# IfcSlab: EB 02 Bodenplatte Einstellräume 535, Decke-005
In: UG1
Pset_SlabCommon - Compartmentation: yes; FireRating: ND; IsExternal: yes; LoadBearing: yes; Status: Neu; ThermalTransmittance: 2.76
Qto_SlabBaseQuantities - Width: 0.535 m; Perimeter: 52.1351 m; GrossArea: 107.359 m2; NetArea: 88.607 m2; GrossVolume: 65.8144 m3; NetVolume: 55.7819 m3

# IfcSlab: Stahlbeton Decke 200 (11)
Material: Stahlbeton Decke
Pset_SlabCommon - FireRating: ND; LoadBearing: yes; Status: Neu; ThermalTransmittance: 2.84
Qto_SlabBaseQuantities - Width: 0.2 m; Stahlbeton Decke, Width: 0.2 m
Name | In | Compartmentation | IsExternal | Perimeter (m) | GrossArea (m2) | NetArea (m2) | GrossVolume (m3) | NetVolume (m3)
Decke-005 | UG1 | yes | no | 61.5428 | 228.96 | 208.513 | 45.792 | 41.7026
Decke-005 | UG1 | yes | yes | 16.751 | 6.58018 | 6.58018 | 1.31604 | 1.31604
Decke-005 | EG | no | yes | 5.58126 | 1.92422 | 1.92422 | 0.384845 | 0.384845
Decke-005 | EG | yes | no | 66.9012 | 242.831 | 229.498 | 48.5662 | 45.8997
Decke-005 | EG | no | yes | 15.4656 | 9.25826 | 9.25826 | 1.85165 | 1.85165
Decke-005 | EG | no | yes | 22.2471 | 20.8735 | 20.8735 | 4.1747 | 4.1747
Decke-005 | EG | no | yes | 15.5296 | 10.4623 | 10.4623 | 2.09245 | 2.09245
Decke-005 | OG1 | yes | no | 66.9077 | 242.839 | 229.506 | 48.5677 | 45.9012
Decke-005 | OG1 | no | yes | 21.9404 | 20.5186 | 20.5186 | 4.10373 | 4.10373
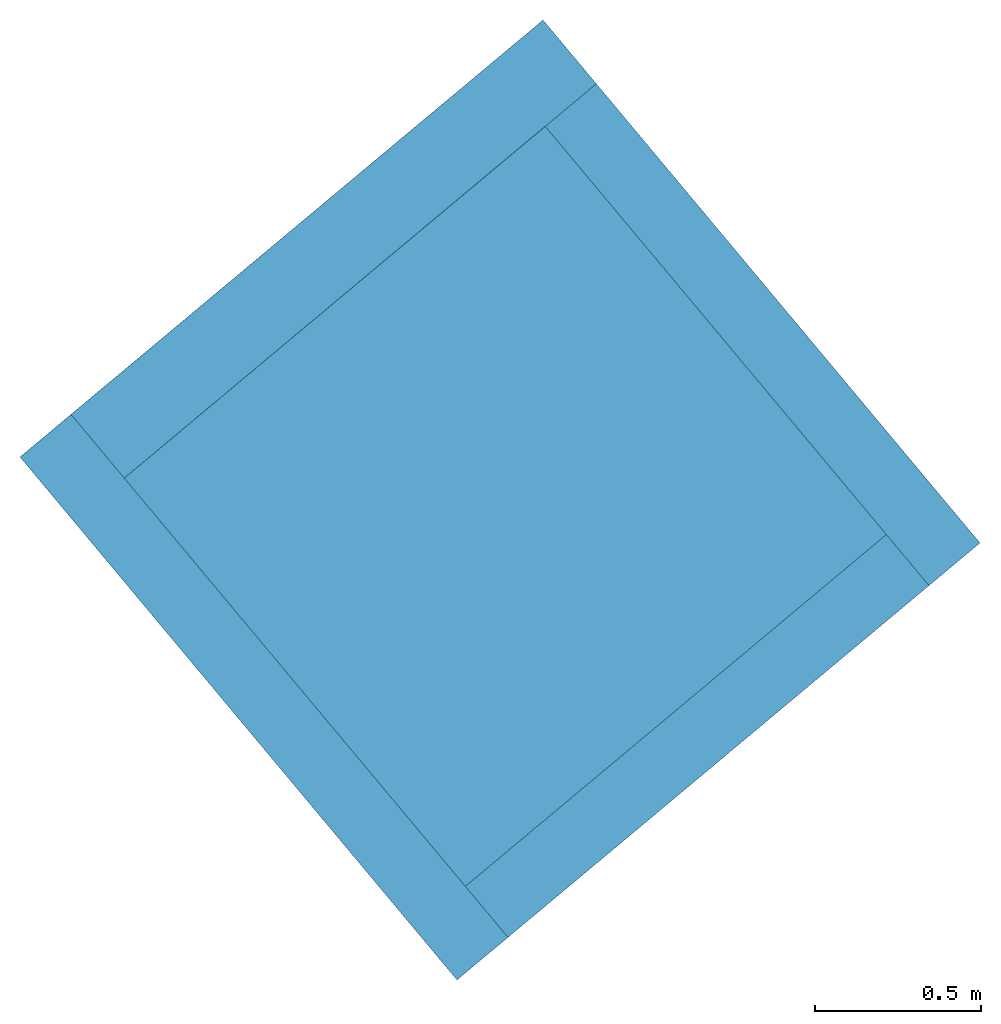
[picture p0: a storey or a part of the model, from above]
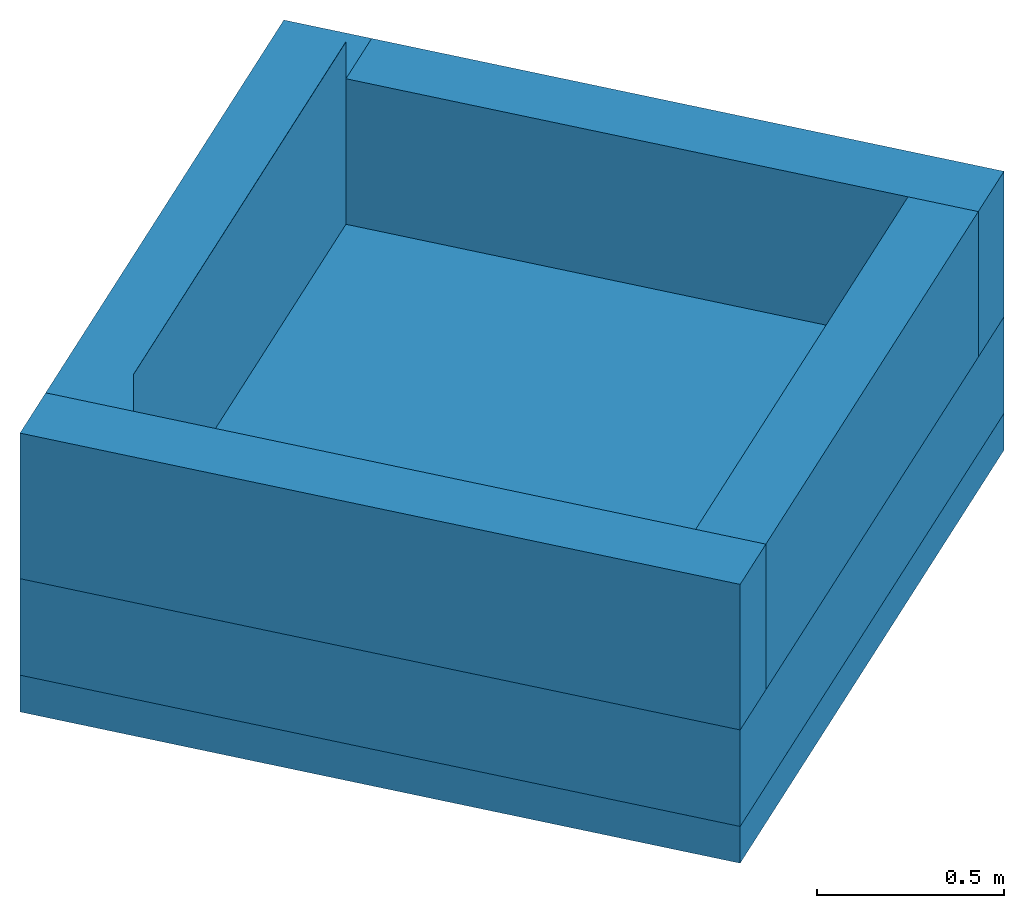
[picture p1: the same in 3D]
Properties of the parts of a building model (IFC4), part 2 of 2

# IfcSlab: Stahlbeton Decke 200 (11)
Name | In | Compartmentation | IsExternal | Perimeter (m) | GrossArea (m2) | NetArea (m2) | GrossVolume (m3) | NetVolume (m3)
Decke-005 | OG1 | no | yes | 15.5296 | 10.4623 | 10.4623 | 2.09245 | 2.09245
Decke-005 | DG1 | yes | no | 60.6875 | 190.754 | 179.901 | 38.3223 | 36.1519

# IfcSlab: Stahlbeton Decke Garage 200 (3)
In: EG
Material: Stahlbeton Decke Garage
Pset_SlabCommon - Compartmentation: yes; FireRating: ND; IsExternal: yes; LoadBearing: yes; Status: Neu; ThermalTransmittance: 2.84
Qto_SlabBaseQuantities - Width: 0.2 m; Stahlbeton Decke Garage, Width: 0.2 m
Name | Perimeter (m) | GrossArea (m2) = NetArea (m2) | GrossVolume (m3) = NetVolume (m3)
Dach-001 | 14.484 | 12.7618 | 2.54466
Dach-001 | 9.62958 | 10.6051 | 2.1202
Dach-001 | 18.7404 | 20.7531 | 4.13898

# IfcSlab: Stahlbeton Decke Garage 250, Dach-001
In: EG
Material: Stahlbeton Decke Garage
Pset_SlabCommon - Compartmentation: yes; FireRating: ND; IsExternal: yes; LoadBearing: yes; Status: Neu; ThermalTransmittance: 2.84
Qto_SlabBaseQuantities - Width: 0.25 m; Perimeter: 44.1688 m; GrossArea: 103.464 m2; NetArea: 103.464 m2; GrossVolume: 25.8503 m3; NetVolume: 25.8503 m3; Stahlbeton Decke Garage, Width: 0.25 m

# IfcSlab: Vorsatzschale Garage 130, Decke-005
In: DG1
Pset_SlabCommon - Compartmentation: no; FireRating: ND; IsExternal: no; LoadBearing: no; Status: Neu; ThermalTransmittance: 0.3
Qto_SlabBaseQuantities - Width: 0.13 m; Perimeter: 10.35 m; GrossArea: 6.19516 m2; NetArea: 6.19516 m2; GrossVolume: 0.805371 m3; NetVolume: 0.805371 m3

# IfcSolarDevice: Flach-Sonnenkollektor 25 (4)
In: DA
Pset_SolarDeviceTypeCommon - Status: Neu

# IfcStair: Treppentyp (4)
Pset_StairCommon - FireExit: yes; FireRating: REI 60; HandicapAccessible: no; IsExternal: no; LoadBearing: yes; NumberOfRiser: 18; NumberOfTreads: 17; RequiredHeadroom: 2.5 m; Status: Neu
ZDB_StairData - TypeOfStair: Main staircase
Name | In
Treppe - 001 | UG1
Treppe - 001 | EG
Treppe - 001 | OG1
Treppe - 001 | DG1

# IfcWall: AW DG 220 (3)
In: DG2
Pset_WallCommon - Brandwiderstand: REI 90; Compartmentation: yes; ExtendToStructure: yes; FireRating: REI 90; IsExternal: no; LoadBearing: yes; Status: Neu; SurfaceSpreadOfFlame: A1; ThermalTransmittance: 2.84
Qto_WallBaseQuantities - Width: 0.22 m
Name | Length (m) | Height (m) | GrossFootprintArea (m2) = NetFootprintArea (m2) | GrossSideArea (m2) = NetSideArea (m2) | GrossVolume (m3) = NetVolume (m3)
Wand-003 | 1.91246 | 0.689938 | 0.361024 | 1.16903 | 0.257187
Wand-003 | 1.49568 | 3.18 | 0.286924 | 4.17834 | 0.905337
Wand-003 | 3.51523 | 2.49 | 0.775351 | 8.50393 | 1.93062

# IfcWall: AW EG 420 (39)
Pset_WallCommon - Brandwiderstand: REI 90; Compartmentation: yes; FireRating: REI 90; IsExternal: yes; LoadBearing: yes; Status: Neu; SurfaceSpreadOfFlame: A1
Qto_WallBaseQuantities - Width: 0.42 m
Name | In | ExtendToStructure | ThermalTransmittance | Length (m) | Height (m) | GrossFootprintArea (m2) = NetFootprintArea (m2) | GrossSideArea (m2) | NetSideArea (m2) | GrossVolume (m3) | NetVolume (m3)
Wand-002 | EG | yes | 0.17 | 12.7826 | 2.76 | 2.8077 | 35.2662 | 19.6232 | 14.8176 | 8.25108
Wand-002 | EG | yes | 0.17 | 17.3323 | 2.76 | 2.70058 | 47.5167 | 20.1383 | 19.8673 | 8.37614
Wand-002 | EG | yes | 0.17 | 12.7713 | 2.76 | 5.36396 | 35.2097 | 31.5197 | 14.8039 | 13.2562
Wand-002 | EG | yes | 0.17 | 17.3323 | 2.76 | 6.03052 | 47.023 | 39.0863 | 20.3048 | 16.9744
Wand-002 | OG1 | yes | 0.17 | 12.9908 | 3.16 | 5.45312 | 37.7138 | 31.2728 | 16.0077 | 13.3025
Wand-002 | OG1 | yes | 0.17 | 6.10967 | 3.16 | 1.93941 | 16.6478 | 8.69717 | 7.51188 | 4.25348
Wand-002 | OG1 | yes | 0.17 | 6.35774 | 3.16 | 2.7505 | 18.8494 | 12.7474 | 8.15398 | 5.59114
Wand-002 | OG1 | yes | 0.17 | 0.938214 | 3.16 | 0.39405 | 2.54256 | 2.54256 | 1.11619 | 1.11619
Wand-002 | OG1 | yes | 0.17 | 1.06173 | 3.16 | 0.445928 | 3.14271 | 3.14271 | 1.32135 | 1.32135
Wand-003 | OG1 | yes | 0.17 | 7.7897 | 3.16 | 3.27167 | 23.1248 | 17.0228 | 9.71987 | 7.15703
Wand-002 | OG1 | yes | 0.17 | 6.66166 | 3.16 | 2.71765 | 19.7311 | 18.2621 | 8.07443 | 7.45745
Wand-002 | OG1 | yes | 0.17 | 1.36144 | 3.16 | 0.652052 | 3.91561 | 3.91561 | 1.89294 | 1.89294
Wand-003 | OG1 | yes | 0.17 | 5.27975 | 3.16 | 2.13724 | 15.6646 | 14.1956 | 6.35439 | 5.73741
Wand-003 | OG1 | yes | 0.17 | 18.3971 | 3.16 | 6.40949 | 52.068 | 28.0209 | 22.2595 | 12.3014
Wand-002 | DG1 | yes | 0.17 | 13.0522 | 2.96 | 5.55041 | 36.4678 | 32.603 | 15.9132 | 14.2989
Wand-002 | DG1 | yes | 0.17 | 12.9813 | 2.96 | 4.78538 | 33.9034 | 24.5643 | 14.7267 | 10.8538
Wand-003 | DG1 | yes | 2.84 | 1.90611 | 2.96 | 0.761442 | 5.44028 | 5.44028 | 2.17963 | 2.17963
Wand-002 | DG1 | yes | 0.17 | 11.1597 | 2.96 | 4.64659 | 31.4809 | 19.1824 | 13.4112 | 8.28265
Wand-002 | DG1 | yes | 0.17 | 7.50702 | 2.96 | 2.35541 | 20.9055 | 12.0137 | 8.9994 | 5.32048
Wand-002 | DG1 | yes | 0.17 | 5.52268 | 2.96 | 2.31953 | 15.8216 | 9.71956 | 6.64818 | 4.08534
Wand-002 | DG1 | yes | 0.17 | 1.83253 | 2.76 | 0.728225 | 2.43662 | 2.43662 | 0.966542 | 0.966542
Wand-002 | DG1 | yes | 0.17 | 2.04614 | 2.96 | 0.819253 | 5.83443 | 5.83443 | 2.34249 | 2.34249
Wand-002 | DG2 | yes | 0.17 | 3.75989 | 2.69 | 1.57915 | 10.1109 | 8.0109 | 4.24526 | 3.36326
Wand-002 | DG2 | yes | 0.17 | 1.67733 | 1.664 | 0.664355 | 2.69561 | 2.69561 | 1.05187 | 1.05187
Wand-002 | DG2 | yes | 0.17 | 9.66105 | 3.18 | 4.09777 | 25.6739 | 25.6739 | 10.9073 | 10.9073
Wand-002 | DG2 | yes | 0.17 | 2.00623 | 2.69 | 0.88274 | 5.40347 | 5.40347 | 2.37457 | 2.37457
Wand-002 | DG2 | yes | 0.17 | 6.5022 | 3.18 | 2.73092 | 20.6611 | 16.5931 | 8.68434 | 6.97578
Wand-002 | DG2 | yes | 0.17 | 7.51206 | 3.18 | 2.38116 | 23.0452 | 12.0879 | 10.1352 | 5.60103
Wand-002 | DG2 | yes | 0.17 | 3.212 | 3.38 | 1.43814 | 5.06912 | 5.06912 | 2.21258 | 2.21258
Wand-002 | DG2 | yes | 0.17 | 5.52373 | 3.18 | 1.48797 | 17.166 | 10.256 | 7.36599 | 4.42363
Wand-002 | DG2 | yes | 0.17 | 5.67021 | 3.18 | 1.56499 | 17.2955 | 12.451 | 7.49133 | 5.4042
Wand-002 | DG2 | yes | 0.17 | 3.27674 | 3.18 | 0.672172 | 8.13476 | 8.13476 | 3.24954 | 3.24954
Wand-002 | DG2 | yes | 0.17 | 1.26454 | 1.864 | 0.617231 | 2.07076 | 2.07076 | 0.97447 | 0.97447
Wand-002 | DG2 | yes | 0.17 | 2.05474 | 2.69 | 0.822867 | 5.25828 | 5.25828 | 2.21102 | 2.21102
Wand-002 | DG2 | no | 0.17 | 2.05968 | 1.45 | 0.945317 | 2.99379 | 2.99379 | 1.37071 | 1.37071
Wand-002 | DG2 | no | 0.17 | 2.01111 | 1.45 | 0.844667 | 2.90886 | 2.90886 | 1.22477 | 1.22477
Wand-002 | DG2 | no | 0.17 | 2.05956 | 1.45 | 0.865014 | 2.97911 | 2.97911 | 1.25427 | 1.25427
Wand-002 | DG2 | yes | 0.17 | 2.57054 | 2.57065 | 0 | 3.30404 | 3.30404 | 1.3877 | 1.3877
Wand-002 | DG2 | no | 0.17 | 2.01115 | 1.45 | 0.764432 | 2.89442 | 2.89442 | 1.10843 | 1.10843

# IfcWall: AW KG 420 (2)
In: UG1
Pset_WallCommon - Brandwiderstand: REI 90; Compartmentation: yes; ExtendToStructure: yes; FireRating: REI 90; IsExternal: yes; LoadBearing: yes; Status: Neu; SurfaceSpreadOfFlame: A1; ThermalTransmittance: 0.39
Qto_WallBaseQuantities - Width: 0.42 m
Name | Length (m) | Height (m) | GrossFootprintArea (m2) = NetFootprintArea (m2) | GrossSideArea (m2) = NetSideArea (m2) | GrossVolume (m3) = NetVolume (m3)
Wand-002 | 5.17009 | 3.28 | 2.15852 | 14.1047 | 6.27556
Wand-002 | 11.9906 | 3.08 | 3.03259 | 23.839 | 10.149

# IfcWall: Aluminium 50 (2)
In: UG1
Material: Aluminium
Pset_WallCommon - Brandwiderstand: ND; Compartmentation: no; ExtendToStructure: no; FireRating: ND; IsExternal: no; LoadBearing: no; Status: Neu; SurfaceSpreadOfFlame: A1; ThermalTransmittance: 0
Qto_WallBaseQuantities - Height: 2.75 m; Width: 0.05 m; Aluminium, Width: 0.05 m
Name | Length (m) | GrossFootprintArea (m2) = NetFootprintArea (m2) | GrossSideArea (m2) = NetSideArea (m2) | GrossVolume (m3) = NetVolume (m3)
Wand-009 | 1.9418 | 0.08584 | 4.7212 | 0.23606
Wand-008 | 3.03511 | 0.153005 | 8.4153 | 0.420765

# IfcWall: Aluminium 80 (3)
In: EG
Material: Aluminium
Pset_WallCommon - Brandwiderstand: ND; Compartmentation: no; ExtendToStructure: no; FireRating: ND; IsExternal: yes; LoadBearing: no; Status: Neu; SurfaceSpreadOfFlame: A1; ThermalTransmittance: 0
Qto_WallBaseQuantities - Height: 2.54 m; Width: 0.08 m; Aluminium, Width: 0.08 m
Name | Length (m) | GrossFootprintArea (m2) = NetFootprintArea (m2) | GrossSideArea (m2) | NetSideArea (m2) | GrossVolume (m3) | NetVolume (m3)
Wand-008 | 1.14446 | 0.0915565 | 2.90692 | 2.90692 | 0.232554 | 0.232554
Wand-008 | 4.69102 | 0.0232014 | 12.0168 | 2.95714 | 0.961343 | 0.236572
Wand-008 | 1.10446 | 0.0851565 | 2.70372 | 2.70372 | 0.216298 | 0.216298

# IfcWall: Balkon Dämmung runter 574 x 610 (4)
Pset_WallCommon - Brandwiderstand: ND; Compartmentation: no; ExtendToStructure: no; FireRating: ND; IsExternal: yes; LoadBearing: yes; Status: Neu; SurfaceSpreadOfFlame: A1; ThermalTransmittance: 0.17
Qto_WallBaseQuantities - Height: 0.610006 m; Width: 0.573552 m
Name | In | Length (m) | GrossFootprintArea (m2) = NetFootprintArea (m2) | GrossSideArea (m2) = NetSideArea (m2) | GrossVolume (m3) = NetVolume (m3)
Wand-004 | OG1 | 1.46467 | 0.766397 | 1.96358 | 0.342115
Wand-004 | OG1 | 2.13228 | 1.19976 | 2.93628 | 0.518229
Wand-004 | DG1 | 1.46467 | 0.766397 | 1.96358 | 0.342115
Wand-004 | DG1 | 2.13347 | 1.20038 | 2.9379 | 0.518506

# IfcWall: Bauteil - Attika 574 x 1710, Träger-001
In: DA
Pset_WallCommon - Brandwiderstand: REI 90; Compartmentation: yes; ExtendToStructure: yes; FireRating: REI 90; IsExternal: yes; LoadBearing: yes; Status: Neu; SurfaceSpreadOfFlame: A1; ThermalTransmittance: 0.17
Qto_WallBaseQuantities - NetVolume: 0.893162 m3; GrossVolume: 0.893198 m3

# IfcWall: Bauteil - Attika 574 x 610 (5)
In: DA
Pset_WallCommon - Brandwiderstand: ND; Compartmentation: no; ExtendToStructure: no; FireRating: ND; IsExternal: yes; LoadBearing: yes; Status: Neu; SurfaceSpreadOfFlame: A1; ThermalTransmittance: 0.17
Qto_WallBaseQuantities - Height: 0.610006 m; Width: 0.573552 m
Name | Length (m) | GrossFootprintArea (m2) = NetFootprintArea (m2) | GrossSideArea (m2) = NetSideArea (m2) | GrossVolume (m3) = NetVolume (m3)
Wand-002 | 1.95913 | 1.18893 | 2.65894 | 0.560267
Wand-002 | 1.91059 | 1.16394 | 2.5931 | 0.546677
Wand-002 | 1.9106 | 1.01551 | 2.45758 | 0.488383
Wand-004 | 3.53906 | 1.82262 | 4.80106 | 1.01568
Wand-002 | 1.95901 | 1.33731 | 2.7943 | 0.618528

# IfcWall: Bauteil - Attika Abschluss wand 264 x 407 (3)
Pset_WallCommon - Brandwiderstand: ND; Compartmentation: no; ExtendToStructure: no; FireRating: ND; IsExternal: yes; LoadBearing: yes; Status: Neu; SurfaceSpreadOfFlame: A1; ThermalTransmittance: 0.17
Name | In | Length (m) | Height (m) | Width (m) | GrossFootprintArea (m2) = NetFootprintArea (m2) | GrossSideArea (m2) = NetSideArea (m2) | GrossVolume (m3) | NetVolume (m3)
Wand-003 | DG1 | 4.21879 | 0.407484 | 0.264398 | 0.920943 | 3.04867 | 0.362714 | 0.362714
Wand-002 | DG1 | 4.28013 | 0.407484 | 0.264398 | 0.920229 | 3.16859 | 0.367682 | 0.367682
Träger-001 | DA | 1.25954 |  |  | 0.226674 |  | 0.126971 | 0.0871271

# IfcWall: Bauteil - Attika Balkon 356 x 610 (10)
Pset_WallCommon - Brandwiderstand: ND; Compartmentation: no; ExtendToStructure: no; FireRating: ND; IsExternal: yes; LoadBearing: yes; Status: Neu; SurfaceSpreadOfFlame: A1; ThermalTransmittance: 2.84
Qto_WallBaseQuantities - Height: 0.610056 m; Width: 0.356308 m
Name | In | Length (m) | GrossFootprintArea (m2) = NetFootprintArea (m2) | GrossSideArea (m2) = NetSideArea (m2) | GrossVolume (m3) = NetVolume (m3)
Wand-002 | OG1 | 5.98147 | 1.94398 | 6.91988 | 0.690764
Wand-002 | OG1 | 1.21099 | 0.387779 | 1.38721 | 0.129251
Wand-003 | OG1 | 0.526483 | 0.225663 | 0.672368 | 0.0707949
Wand-003 | OG1 | 5.84895 | 1.94355 | 6.75761 | 0.661552
Wand-003 | OG1 | 8.55286 | 2.81354 | 9.82631 | 0.965632
Wand-003 | OG1 | 2.13664 | 0.679352 | 2.44741 | 0.234455
Wand-003 | DG1 | 8.39793 | 2.76474 | 9.64882 | 0.948022
Wand-003 | DG1 | 2.24094 | 0.754676 | 2.62619 | 0.245493
Wand-003 | DG1 | 0.786758 | 0.384333 | 0.929916 | 0.0880714
Wand-004 | DG1 | 5.84895 | 1.92855 | 6.75761 | 0.661552

# IfcWall: Bauteil - Attika Stehfalz 574 x 670, Wand-004
In: DA
Pset_WallCommon - Brandwiderstand: ND; Compartmentation: no; ExtendToStructure: no; FireRating: ND; IsExternal: yes; LoadBearing: yes; Status: Neu; SurfaceSpreadOfFlame: A1; ThermalTransmittance: 0.17
Qto_WallBaseQuantities - Length: 11.7621 m; Height: 0.670006 m; Width: 0.573552 m; GrossFootprintArea: 6.19912 m2; NetFootprintArea: 6.19912 m2; GrossSideArea: 16.6063 m2; NetSideArea: 16.6063 m2; GrossVolume: 3.57929 m3; NetVolume: 3.57929 m3

# IfcWall: Bauteil - Attika Terrasse 1.DG 574 x 410 (16)
Pset_WallCommon - Brandwiderstand: ND; Compartmentation: no; ExtendToStructure: no; FireRating: ND; IsExternal: yes; LoadBearing: yes; Status: Neu; SurfaceSpreadOfFlame: A1; ThermalTransmittance: 0.17
Qto_WallBaseQuantities - Height: 0.410006 m; Width: 0.573552 m
Name | In | Length (m) | GrossFootprintArea (m2) = NetFootprintArea (m2) | GrossSideArea (m2) = NetSideArea (m2) | GrossVolume (m3) = NetVolume (m3)
Wand-003 | DG1 | 0.215447 | 0.18993 | 0.258363 | 0.0487188
Wand-002 | DG1 | 0.677915 | 0.513336 | 0.831879 | 0.15092
Wand-003 | DG1 | 6.60639 | 3.41806 | 7.56967 | 1.21824
Wand-003 | DG1 | 0.801363 | 0.576915 | 0.974676 | 0.174011
Wand-004 | DG1 | 7.73432 | 3.99895 | 8.87424 | 1.42916
Wand-004 | DG1 | 0.214999 | 0.110724 | 0.248666 | 0.040203
Wand-004 | DG1 | 1.10118 | 0.73132 | 1.32143 | 0.230068
Wand-004 | DG1 | 5.17919 | 2.84727 | 5.9668 | 0.975525
Wand-005 | DG1 | 1.10116 | 0.582874 | 1.20238 | 0.188814
Wand-004 | DG2 | 2.92269 | 1.6694 | 3.42817 | 0.570676
Wand-004 | DG2 | 7.24688 | 3.74792 | 8.31046 | 1.33801
Wand-005 | DG2 | 1.35108 | 0.711577 | 1.49142 | 0.235543
Wand-004 | DG2 | 5.42216 | 3.12083 | 6.36683 | 1.06221
Wand-004 | DG2 | 1.35105 | 0.711563 | 1.49139 | 0.23554
Wand-004 | DG2 | 1.21426 | 0.789554 | 1.45221 | 0.251212
Wand-005 | DG2 | 5.29993 | 2.74524 | 6.05863 | 0.973946

# IfcWall: IW LB 01 Leichtbautrennwand einfach 10,5 cm 105 (57)
Pset_WallCommon - ExtendToStructure: yes; IsExternal: no; LoadBearing: no; Status: Neu; SurfaceSpreadOfFlame: A2; ThermalTransmittance: 0.38
Qto_WallBaseQuantities - Width: 0.105 m
Name | In | Brandwiderstand = FireRating | Compartmentation | Length (m) | Height (m) | GrossFootprintArea (m2) = NetFootprintArea (m2) | GrossSideArea (m2) | NetSideArea (m2) | GrossVolume (m3) | NetVolume (m3)
Wand-012 | EG | EI 60 | yes | 2.04998 | 2.76 | 0.121798 | 5.65794 | 3.64209 | 0.594083 | 0.382419
Wand-012 | EG | EI 30 | no | 5.71426 | 2.76 | 0.413097 | 15.7713 | 11.7396 | 1.65599 | 1.23266
Wand-012 | EG | EI 30 | no | 4.80592 | 2.76 | 0.504621 | 13.2643 | 13.2643 | 1.39275 | 1.39275
Wand-012 | EG | EI 30 | no | 3.20025 | 2.76 | 0.336027 | 8.8327 | 8.8327 | 0.927433 | 0.927433
Wand-012 | EG | EI 60 | yes | 2.02595 | 2.76 | 0.181222 | 4.76354 | 4.76354 | 0.500171 | 0.500171
Wand-012 | EG | EI 30 | no | 2.69484 | 2.76 | 0.0960586 | 7.43777 | 3.40607 | 0.780966 | 0.357637
Wand-012 | EG | EI 30 | no | 1.9928 | 2.76 | 0.108257 | 5.37593 | 3.36008 | 0.55671 | 0.345046
Wand-012 | EG | EI 30 | no | 5.59294 | 2.76 | 0.496846 | 15.4572 | 13.4414 | 1.62922 | 1.41755
Wand-012 | EG | EI 60 | yes | 3.38252 | 2.76 | 0.227177 | 8.76307 | 6.52072 | 0.913912 | 0.678465
Wand-012 | EG | EI 60 | yes | 3.4371 | 2.76 | 0.363933 | 9.5071 | 9.5071 | 1.00446 | 1.00446
Wand-012 | EG | EI 30 | no | 3.23168 | 2.76 | 0.339326 | 8.91943 | 8.91943 | 0.93654 | 0.93654
Wand-012 | EG | EI 60 | yes | 2.64394 | 2.76 | 0.178351 | 7.17999 | 5.01999 | 0.770457 | 0.543657
Wand-012 | EG | EI 60 | yes | 5.00711 | 2.76 | 0.338847 | 13.8196 | 9.78793 | 1.45106 | 1.02773
Wand-012 | EG | EI 60 | yes | 2.92356 | 2.76 | 0.210486 | 8.04832 | 6.03247 | 0.838863 | 0.627199
Wand-012 | EG | EI 30 | no | 0.546188 | 2.76 | 0.0543122 | 1.48678 | 1.48678 | 0.149902 | 0.149902
Wand-012 | EG | EI 30 | no | 1.33849 | 2.76 | 0.143579 | 3.71493 | 3.71493 | 0.396277 | 0.396277
Wand-012 | OG1 | EI 30 | yes | 2.92356 | 2.76 | 0.210486 | 8.04832 | 6.03247 | 0.838863 | 0.627199
Wand-012 | OG1 | EI 30 | no | 0.546188 | 2.76 | 0.0543122 | 1.48678 | 1.48678 | 0.149902 | 0.149902
Wand-012 | OG1 | EI 60 | yes | 5.00711 | 2.76 | 0.338847 | 13.8196 | 9.78793 | 1.45106 | 1.02773
Wand-012 | OG1 | EI 30 | no | 1.33849 | 2.76 | 0.143579 | 3.71493 | 3.71493 | 0.396277 | 0.396277
Wand-012 | OG1 | EI 30 | yes | 2.64394 | 2.76 | 0.178351 | 7.17999 | 5.01999 | 0.770457 | 0.543657
Wand-012 | OG1 | EI 30 | yes | 2.04998 | 2.76 | 0.121798 | 5.65794 | 3.64209 | 0.594083 | 0.382419
Wand-012 | OG1 | EI 30 | no | 5.71426 | 2.76 | 0.413097 | 15.7713 | 11.7396 | 1.65599 | 1.23266
Wand-012 | OG1 | EI 30 | no | 4.80592 | 2.76 | 0.504621 | 13.2643 | 13.2643 | 1.39275 | 1.39275
Wand-012 | OG1 | EI 30 | no | 3.20025 | 2.76 | 0.336027 | 8.8327 | 8.8327 | 0.927433 | 0.927433
Wand-012 | OG1 | EI 60 | yes | 2.02595 | 2.76 | 0.181222 | 4.76354 | 4.76354 | 0.500171 | 0.500171
Wand-012 | OG1 | EI 30 | no | 2.69484 | 2.76 | 0.0960586 | 7.43777 | 3.40607 | 0.780966 | 0.357637
Wand-012 | OG1 | EI 30 | no | 1.99284 | 2.76 | 0.108261 | 5.37604 | 3.36019 | 0.556721 | 0.345057
Wand-012 | OG1 | EI 30 | no | 7.1594 | 2.76 | 0.639798 | 19.2148 | 17.1989 | 2.02376 | 1.8121
Wand-012 | OG1 | EI 30 | yes | 3.38252 | 2.76 | 0.227177 | 8.76307 | 6.52072 | 0.913912 | 0.678465
Wand-012 | OG1 | EI 30 | yes | 3.4371 | 2.76 | 0.363933 | 9.5071 | 9.5071 | 1.00446 | 1.00446
Wand-012 | OG1 | EI 30 | no | 4.16988 | 2.76 | 0.437838 | 11.5089 | 11.5089 | 1.20843 | 1.20843
Wand-012 | DG1 | EI 60 | yes | 2.92355 | 2.76 | 0.210486 | 8.04831 | 6.03246 | 0.838863 | 0.627198
Wand-012 | DG1 | EI 60 | yes | 5.00711 | 2.76 | 0.338847 | 13.8196 | 9.78793 | 1.45106 | 1.02773
Wand-012 | DG1 | EI 60 | yes | 2.57663 | 2.76 | 0.172784 | 7.13221 | 4.97221 | 0.755092 | 0.528292
Wand-012 | DG1 | EI 30 | no | 0.790943 | 2.76 | 0.0800115 | 2.1623 | 2.1623 | 0.220832 | 0.220832
Wand-012 | DG1 | EI 30 | no | 1.3367 | 2.76 | 0.143391 | 3.70999 | 3.70999 | 0.395759 | 0.395759
Wand-012 | DG1 | EI 30 | yes | 2.04998 | 2.76 | 0.121798 | 5.65794 | 3.64209 | 0.594083 | 0.382419
Wand-012 | DG1 | EI 30 | no | 5.71926 | 2.76 | 0.507068 | 15.7851 | 13.7693 | 1.65744 | 1.44577
Wand-012 | DG1 | EI 30 | no | 3.18327 | 2.76 | 0.334244 | 8.78584 | 8.78584 | 0.922513 | 0.922513
Wand-012 | DG1 | EI 30 | no | 3.20025 | 2.76 | 0.336027 | 8.8327 | 8.8327 | 0.927433 | 0.927433
Wand-012 | DG1 | EI 60 | yes | 2.02595 | 2.76 | 0.181222 | 4.76354 | 4.76354 | 0.500171 | 0.500171
Wand-012 | DG1 | EI 30 | no | 2.69484 | 2.76 | 0.0960586 | 7.43777 | 3.40607 | 0.780966 | 0.357637
Wand-012 | DG1 | EI 30 | no | 1.99279 | 2.76 | 0.108255 | 5.37589 | 3.36004 | 0.556706 | 0.345042
Wand-012 | DG1 | EI 30 | no | 5.59294 | 2.76 | 0.496846 | 15.4572 | 13.4414 | 1.62922 | 1.41755
Wand-012 | DG1 | EI 30 | yes | 3.38252 | 2.76 | 0.227177 | 8.76307 | 6.52072 | 0.913912 | 0.678465
Wand-012 | DG1 | EI 30 | yes | 3.4371 | 2.76 | 0.363933 | 9.5071 | 9.5071 | 1.00446 | 1.00446
Wand-012 | DG1 | EI 30 | no | 3.23168 | 2.76 | 0.339326 | 8.91943 | 8.91943 | 0.93654 | 0.93654
Wand-012 | DG2 | EI 30 | no | 3.76763 | 2.98 | 0.395601 | 11.2275 | 11.2275 | 1.17889 | 1.17889
Wand-012 | DG2 | EI 30 | no | 3.96322 | 2.98 | 0.309414 | 11.4975 | 9.48166 | 1.20053 | 0.988869
Wand-013 | DG2 | EI 30 | no | 1.70064 | 2.98 | 0.181605 | 5.09026 | 5.09026 | 0.541182 | 0.541182
Wand-014 | DG2 | EI 30 | no | 2.2232 | 2.98 | 0.136948 | 6.60278 | 4.58693 | 0.686587 | 0.474922
Wand-012 | DG2 | EI 30 | no | 4.50347 | 2.98 | 0.379415 | 13.4203 | 11.4045 | 1.40914 | 1.19747
Wand-013 | DG2 | EI 30 | no | 1.71446 | 2.98 | 0.0896057 | 5.13144 | 3.11559 | 0.545506 | 0.333842
Wand-014 | DG2 | EI 30 | no | 2.67539 | 2.98 | 0.277879 | 7.95032 | 7.95032 | 0.828079 | 0.828079
Wand-013 | DG2 | EI 30 | no | 2.40833 | 2.98 | 0.157174 | 6.27087 | 4.25502 | 0.651737 | 0.440072
Wand-014 | DG2 | EI 30 | no | 3.14394 | 2.98 | 0.330112 | 4.92871 | 4.92871 | 0.517514 | 0.517514

# IfcWall: Individuelles Profil 574 x 610 (10)
In: DA
Pset_WallCommon - Brandwiderstand: ND; Compartmentation: no; ExtendToStructure: no; FireRating: ND; IsExternal: yes; LoadBearing: yes; Status: Neu; SurfaceSpreadOfFlame: A1; ThermalTransmittance: 0.17
Qto_WallBaseQuantities - Height: 0.610006 m; Width: 0.573552 m
Name | Length (m) | GrossFootprintArea (m2) = NetFootprintArea (m2) | GrossSideArea (m2) = NetSideArea (m2) | GrossVolume (m3) = NetVolume (m3)
Wand-004 | 5.46965 | 2.99686 | 7.42129 | 1.54318
Wand-005 | 3.41792 | 1.79205 | 4.50527 | 0.899178
Wand-004 | 6.40161 | 3.62525 | 8.82111 | 1.86242
Wand-004 | 2.43483 | 1.37831 | 3.44535 | 0.735735
Wand-004 | 5.42321 | 3.12137 | 7.4938 | 1.58847
Wand-004 | 7.41665 | 3.83677 | 10.0082 | 2.05917
Wand-004 | 0.269033 | 0.13855 | 0.364948 | 0.0753186
Wand-004 | 3.45737 | 1.90468 | 4.69025 | 0.968041
Wand-004 | 6.16703 | 3.356 | 8.36687 | 1.73806
Wand-004 | 4.38944 | 2.27507 | 5.87208 | 1.18814

# IfcWall: Keller-AW 350 (2)
In: UG1
Pset_WallCommon - Brandwiderstand: REI 90; Compartmentation: yes; ExtendToStructure: yes; FireRating: REI 90; IsExternal: yes; LoadBearing: yes; Status: Neu; SurfaceSpreadOfFlame: A1; ThermalTransmittance: 0.39
Qto_WallBaseQuantities - Height: 3.08 m; Width: 0.35 m
Name | Length (m) | GrossFootprintArea (m2) = NetFootprintArea (m2) | GrossSideArea (m2) = NetSideArea (m2) | GrossVolume (m3) = NetVolume (m3)
Wand-002 | 20.0126 | 7.00441 | 61.6388 | 21.5736
Wand-002 | 20.1073 | 7.30759 | 62.7262 | 22.1388

# IfcWall: LB 10,5 cm doppelte Vorsatzschale Bad + STB 305 (5)
Pset_WallCommon - Brandwiderstand: REI 90; Compartmentation: yes; ExtendToStructure: yes; FireRating: REI 90; IsExternal: no; LoadBearing: yes; Status: Neu; SurfaceSpreadOfFlame: A1; ThermalTransmittance: 2.84
Qto_WallBaseQuantities - Height: 2.76 m; Width: 0.305 m
Name | In | Length (m) | GrossFootprintArea (m2) = NetFootprintArea (m2) | GrossSideArea (m2) = NetSideArea (m2) | GrossVolume (m3) = NetVolume (m3)
Wand-003 | EG | 1.94499 | 0.594222 | 5.37507 | 1.64005
Wand-003 | EG | 1.93367 | 0.575831 | 5.33692 | 1.58929
Wand-003 | OG1 | 1.94499 | 0.594222 | 5.37507 | 1.64005
Wand-003 | DG1 | 1.94499 | 0.594222 | 5.37507 | 1.64005
Wand-003 | DG1 | 2.13375 | 0.61473 | 5.50964 | 1.69665

# IfcWall: LB 10,5 cm doppelte Vorsatzschale Bad 105 (19)
Pset_WallCommon - Compartmentation: yes; ExtendToStructure: yes; IsExternal: no; LoadBearing: no; Status: Neu; SurfaceSpreadOfFlame: A2; ThermalTransmittance: 0.38
Qto_WallBaseQuantities - Width: 0.105 m
Name | In | Brandwiderstand = FireRating | Length (m) | Height (m) | GrossFootprintArea (m2) = NetFootprintArea (m2) | GrossSideArea (m2) = NetSideArea (m2) | GrossVolume (m3) = NetVolume (m3)
Wand-004 | EG | EI 60 | 0.848074 | 2.76 | 0.0860103 | 2.31999 | 0.237388
Wand-004 | EG | EI 60 | 0.408075 | 2.76 | 0.0458854 | 1.22979 | 0.126644
Wand-004 | EG | EI 90 | 1.80141 | 2.76 | 0.185773 | 4.90978 | 0.512733
Wand-004 | EG | EI 60 | 1.00223 | 2.76 | 0.0964588 | 2.57982 | 0.266223
Wand-004 | EG | EI 60 | 1.19988 | 2.76 | 0.125987 | 3.31167 | 0.347725
Wand-004 | EG | EI 60 | 0.398104 | 2.76 | 0.0346077 | 0.912467 | 0.0955172
Wand-004 | OG1 | EI 60 | 0.398104 | 2.76 | 0.0346077 | 0.912467 | 0.0955171
Wand-004 | OG1 | EI 60 | 1.19988 | 2.76 | 0.125987 | 3.31167 | 0.347725
Wand-004 | OG1 | EI 60 | 0.848074 | 2.76 | 0.0860103 | 2.31999 | 0.237388
Wand-004 | OG1 | EI 60 | 0.408075 | 2.76 | 0.0458854 | 1.22979 | 0.126644
Wand-004 | OG1 | EI 90 | 1.80141 | 2.76 | 0.185773 | 4.90978 | 0.512733
Wand-004 | OG1 | EI 60 | 1.00223 | 2.76 | 0.0964588 | 2.57982 | 0.266223
Wand-004 | DG1 | EI 60 | 0.398104 | 2.76 | 0.0346077 | 0.912467 | 0.0955172
Wand-004 | DG1 | EI 60 | 0.848074 | 2.76 | 0.0860103 | 2.31999 | 0.237388
Wand-004 | DG1 | EI 60 | 0.408075 | 2.76 | 0.0458854 | 1.22979 | 0.126644
Wand-004 | DG1 | EI 90 | 1.80141 | 2.76 | 0.185766 | 4.90962 | 0.512715
Wand-004 | DG1 | EI 60 | 1.00223 | 2.76 | 0.0964588 | 2.57982 | 0.266223
Wand-004 | DG1 | EI 60 | 1.19988 | 2.76 | 0.125987 | 3.31167 | 0.347725
Wand-004 | DG2 | EI 60 | 1.20691 | 2.98 | 0.124476 | 3.5966 | 0.370938

# IfcWall: LB 13 cm doppelte Vorsatzschale Bad 120 (6)
Pset_WallCommon - Brandwiderstand: EI 60; Compartmentation: no; ExtendToStructure: yes; FireRating: EI 60; IsExternal: no; LoadBearing: no; Status: Neu; SurfaceSpreadOfFlame: A2; ThermalTransmittance: 0.38
Qto_WallBaseQuantities - Height: 2.76 m; Width: 0.12 m
Name | In | Length (m) | GrossFootprintArea (m2) = NetFootprintArea (m2) | GrossSideArea (m2) = NetSideArea (m2) | GrossVolume (m3) = NetVolume (m3)
Wand-013 | EG | 2.23037 | 0.271694 | 6.30071 | 0.749876
Wand-013 | EG | 1.37105 | 0.169026 | 3.78409 | 0.46651
Wand-013 | OG1 | 1.37095 | 0.169014 | 3.78382 | 0.466479
Wand-013 | OG1 | 3.37358 | 0.40888 | 9.45598 | 1.12851
Wand-013 | DG1 | 1.37102 | 0.169023 | 3.69832 | 0.466373
Wand-013 | DG1 | 2.23037 | 0.271694 | 6.30071 | 0.749876

# IfcWall: LB 6,5 cm einfach Vorsatzschale + STB + Schale 330 (3)
Pset_WallCommon - Brandwiderstand: REI 90; Compartmentation: yes; ExtendToStructure: yes; FireRating: REI 90; IsExternal: no; LoadBearing: yes; Status: Neu; SurfaceSpreadOfFlame: A1; ThermalTransmittance: 2.84
Qto_WallBaseQuantities - Height: 2.76 m; Width: 0.33 m
Name | In | Length (m) | GrossFootprintArea (m2) = NetFootprintArea (m2) | GrossSideArea (m2) = NetSideArea (m2) | GrossVolume (m3) = NetVolume (m3)
Wand-003 | EG | 7.60274 | 2.4978 | 20.6524 | 6.89394
Wand-003 | OG1 | 7.60274 | 2.4978 | 20.6524 | 6.89394
Wand-003 | DG1 | 7.52674 | 2.48382 | 18.6417 | 6.15178

# IfcWall: LB 6,5 cm einfach Vorsatzschale + STB 265 (9)
Pset_WallCommon - Brandwiderstand: REI 90; Compartmentation: yes; ExtendToStructure: yes; FireRating: REI 90; IsExternal: no; LoadBearing: yes; Status: Neu; SurfaceSpreadOfFlame: A1; ThermalTransmittance: 2.84
Qto_WallBaseQuantities - Width: 0.265 m
Name | In | Length (m) | Height (m) | GrossFootprintArea (m2) = NetFootprintArea (m2) | GrossSideArea (m2) | NetSideArea (m2) | GrossVolume (m3) | NetVolume (m3)
Wand-007 | UG1 | 20.1776 | 2.88 | 4.93226 | 50.6018 | 48.2918 | 13.6562 | 13.0441
Wand-003 | EG | 2.01299 | 2.76 | 0.255879 | 5.81115 | 3.25915 | 1.51077 | 0.834487
Wand-003 | EG | 3.0615 | 2.76 | 0.493298 | 8.17374 | 5.62174 | 2.16604 | 1.48976
Wand-003 | OG1 | 2.96135 | 2.76 | 0.493258 | 8.17332 | 5.62132 | 2.16593 | 1.48965
Wand-003 | OG1 | 2.00553 | 2.76 | 0.25589 | 5.81126 | 3.25926 | 1.5108 | 0.834517
Wand-003 | DG1 | 2.01342 | 2.76 | 0.255544 | 5.77094 | 3.21894 | 1.50984 | 0.833561
Wand-003 | DG1 | 2.96138 | 2.76 | 0.493267 | 8.17342 | 5.62142 | 2.16596 | 1.48968
Wand-003 | DG2 | 1.83286 | 2.49 | 0.215571 | 4.81283 | 2.26083 | 1.26261 | 0.586327
Wand-003 | DG2 | 0.590386 | 2.49 | 0.19339 | 1.43894 | 1.43894 | 0.338303 | 0.338303

# IfcWall: LB 9,0 cm einfache Vorsatzschale + STB 290 (5)
Pset_WallCommon - Brandwiderstand: REI 90; Compartmentation: yes; ExtendToStructure: yes; FireRating: REI 90; IsExternal: no; LoadBearing: yes; Status: Neu; SurfaceSpreadOfFlame: A1; ThermalTransmittance: 2.84
Qto_WallBaseQuantities - Width: 0.29 m
Name | In | Length (m) | Height (m) | GrossFootprintArea (m2) = NetFootprintArea (m2) | GrossSideArea (m2) = NetSideArea (m2) | GrossVolume (m3) = NetVolume (m3)
Wand-003 | EG | 3.27052 | 2.76 | 0.937452 | 9.02665 | 2.58737
Wand-003 | OG1 | 3.27052 | 2.76 | 0.937452 | 9.02665 | 2.58737
Wand-003 | OG1 | 1.93367 | 2.76 | 0.54484 | 5.31623 | 1.50376
Wand-003 | DG1 | 3.16552 | 2.76 | 0.929127 | 8.88175 | 2.56439
Wand-003 | DG2 | 1.64967 | 2.69 | 0.478404 | 4.43761 | 1.28691

# IfcWall: LB 9,0 cm einfache Vorsatzschale 90 (23)
Pset_WallCommon - Brandwiderstand: EI 60; ExtendToStructure: yes; FireRating: EI 60; IsExternal: no; LoadBearing: no; Status: Neu; SurfaceSpreadOfFlame: A2; ThermalTransmittance: 0.41
Qto_WallBaseQuantities - Width: 0.09 m
Name | In | Compartmentation | Length (m) | Height (m) | GrossFootprintArea (m2) = NetFootprintArea (m2) | GrossSideArea (m2) = NetSideArea (m2) | GrossVolume (m3) = NetVolume (m3)
Wand-006 | EG | yes | 1.84114 | 2.76 | 0.162778 | 5.06086 | 0.449267
Wand-006 | EG | yes | 1.89561 | 2.76 | 0.17353 | 5.33538 | 0.478942
Wand-006 | EG | no | 0.154755 | 2.76 | 0.00695302 | 0.282226 | 0.0191903
Wand-006 | EG | no | 1.88614 | 2.76 | 0.168628 | 5.18505 | 0.465412
Wand-006 | EG | yes | 0.948773 | 2.76 | 0.0876396 | 2.70141 | 0.241885
Wand-006 | EG | yes | 1.28718 | 2.76 | 0.11022 | 3.39387 | 0.304206
Wand-006 | OG1 | yes | 1.28718 | 2.76 | 0.11022 | 3.39387 | 0.304206
Wand-006 | OG1 | yes | 1.84114 | 2.76 | 0.162778 | 5.06086 | 0.449267
Wand-006 | OG1 | yes | 1.89561 | 2.76 | 0.17353 | 5.33538 | 0.478942
Wand-006 | OG1 | no | 0.154755 | 2.76 | 0.00695302 | 0.282226 | 0.0191903
Wand-006 | OG1 | no | 1.88614 | 2.76 | 0.168628 | 5.18505 | 0.465412
Wand-006 | OG1 | yes | 0.948773 | 2.76 | 0.0876396 | 2.70141 | 0.241885
Wand-006 | DG1 | yes | 1.22003 | 2.76 | 0.109803 | 3.36729 | 0.303056
Wand-006 | DG1 | yes | 1.85061 | 2.76 | 0.166555 | 5.10768 | 0.459691
Wand-006 | DG1 | yes | 0.948773 | 2.76 | 0.0876396 | 2.70141 | 0.241885
Wand-006 | DG2 | yes | 3.88988 | 2.98 | 0.352339 | 7.16001 | 0.651106
Wand-006 | DG2 | yes | 2.25311 | 2.98 | 0.202773 | 6.71392 | 0.604265
Wand-006 | DG2 | yes | 0.298709 | 2.98 | 0.0313836 | 0.979552 | 0.0935232
Wand-006 | DG2 | yes | 0.704346 | 2.98 | 0.0552911 | 1.92013 | 0.164766
Wand-006 | DG2 | yes | 0.467759 | 2.98 | 0.0438983 | 1.48331 | 0.130816
Wand-006 | DG2 | yes | 0.613427 | 2.98 | 0.0552084 | 1.91741 | 0.164521
Wand-007 | DG2 | yes | 0.377701 | 2.98 | 0.0321931 | 1.21495 | 0.0959355
Wand-006 | DG2 | yes | 3.73042 | 2.49 | 0.312113 | 8.64758 | 0.777162

# IfcWall: LB Dreifach Vorsatzschale Schacht 45 (3)
Pset_WallCommon - Brandwiderstand: EI 90; Compartmentation: yes; ExtendToStructure: yes; FireRating: EI 90; IsExternal: no; LoadBearing: no; Status: Neu; SurfaceSpreadOfFlame: A2; ThermalTransmittance: 2.86
Qto_WallBaseQuantities - Length: 0.245122 m; Width: 0.045 m; GrossFootprintArea: 0.0144055 m2; NetFootprintArea: 0.0144055 m2
Name | In | Height (m) | GrossSideArea (m2) = NetSideArea (m2) | GrossVolume (m3) = NetVolume (m3)
Wand-002 | EG | 2.96 | 0.932561 | 0.0419652
Wand-002 | OG1 | 2.76 | 0.883536 | 0.0397591
Wand-002 | DG1 | 2.76 | 0.883536 | 0.0397591

# IfcWall: Stahlbeton Decke Garage 120 (8)
In: DA
Material: Stahlbeton Decke Garage
Pset_WallCommon - Brandwiderstand: REI 90; Compartmentation: yes; ExtendToStructure: no; FireRating: REI 90; IsExternal: no; LoadBearing: yes; Status: Neu; SurfaceSpreadOfFlame: A1; ThermalTransmittance: 2.84
Qto_WallBaseQuantities - Height: 1 m; Width: 0.12 m; Stahlbeton Decke Garage, Width: 0.12 m
Name | Length (m) | GrossFootprintArea (m2) = NetFootprintArea (m2) = GrossVolume (m3) = NetVolume (m3) | GrossSideArea (m2) = NetSideArea (m2)
Wand-003 | 0.644287 | 0.0917145 | 0.764287
Wand-004 | 0.452701 | 0.0543242 | 0.452701
Wand-005 | 0.643398 | 0.0772077 | 0.643398
Wand-006 | 0.452702 | 0.0399242 | 0.332702
Wand-007 | 1.41979 | 0.184775 | 1.53979
Wand-008 | 0.328734 | 0.0394481 | 0.328734
Wand-009 | 1.42094 | 0.170513 | 1.42094
Wand-010 | 0.326243 | 0.0247492 | 0.206243

# IfcWall: Stahlbeton Decke Garage 250, Wand-004
In: UG1
Material: Stahlbeton Decke Garage
Pset_WallCommon - Brandwiderstand: REI 90; Compartmentation: yes; ExtendToStructure: yes; FireRating: REI 90; IsExternal: yes; LoadBearing: yes; Status: Neu; SurfaceSpreadOfFlame: A1; ThermalTransmittance: 2.84
Qto_WallBaseQuantities - Length: 20.0773 m; Height: 3.08 m; Width: 0.25 m; GrossFootprintArea: 4.95682 m2; NetFootprintArea: 4.95682 m2; GrossSideArea: 61.068 m2; NetSideArea: 61.068 m2; GrossVolume: 15.267 m3; NetVolume: 15.267 m3; Stahlbeton Decke Garage, Width: 0.25 m

# IfcWall: Stahlbeton Wand 150 (4)
In: EG
Material: Stahlbeton Wand
Pset_WallCommon - Status: EXISTING
Qto_WallBaseQuantities - Height: 0.52 m; Width: 0.15 m; Stahlbeton Wand, Width: 0.15 m
Name | Length (m) | GrossFootprintArea (m2) = NetFootprintArea (m2) | GrossSideArea (m2) = NetSideArea (m2) | GrossVolume (m3) = NetVolume (m3)
Wand-008 | 2.99418 | 0.441612 | 1.53092 | 0.229638
Wand-009 | 5.23169 | 0.773503 | 2.68148 | 0.402222
Wand-010 | 1.01213 | 0.15182 | 0.526309 | 0.0789463
Wand-011 | 5.12639 | 0.750193 | 2.60067 | 0.3901

# IfcWall: Stahlbeton Wand 180 (2)
In: EG
Material: Stahlbeton Wand
Pset_WallCommon - Brandwiderstand: REI 90; Compartmentation: no; ExtendToStructure: no; FireRating: REI 90; IsExternal: yes; LoadBearing: yes; Status: Neu; SurfaceSpreadOfFlame: A1; ThermalTransmittance: 2.84
Qto_WallBaseQuantities - Height: 1.4 m; Width: 0.18 m; Stahlbeton Wand, Width: 0.18 m
Name | Length (m) | GrossFootprintArea (m2) = NetFootprintArea (m2) | GrossSideArea (m2) = NetSideArea (m2) | GrossVolume (m3) = NetVolume (m3)
Wand-009 | 1.03745 | 0.190603 | 1.35426 | 0.243767
Wand-011 | 1.10297 | 0.180534 | 1.40415 | 0.252747

# IfcWall: Stahlbeton Wand 200 (37)
Material: Stahlbeton Wand
Pset_WallCommon - Brandwiderstand: REI 90; FireRating: REI 90; LoadBearing: yes; Status: Neu; SurfaceSpreadOfFlame: A1; ThermalTransmittance: 2.84
Qto_WallBaseQuantities - Width: 0.2 m; Stahlbeton Wand, Width: 0.2 m
Name | In | Compartmentation | ExtendToStructure | IsExternal | Length (m) | Height (m) | GrossFootprintArea (m2) = NetFootprintArea (m2) | GrossSideArea (m2) | NetSideArea (m2) | GrossVolume (m3) | NetVolume (m3)
Wand-011 | UG2 | no | no | yes | 1.80042 | 0.475 | 0.360084 | 0.855199 | 0.855199 | 0.17104 | 0.17104
Wand-013 | UG2 | no | no | yes | 1.75076 | 0.475 | 0.330152 | 0.784111 | 0.784111 | 0.156823 | 0.156823
Wand-013 | UG2 | no | no | yes | 1.95051 | 0.475 | 0.410103 | 0.973994 | 0.973994 | 0.194799 | 0.194799
Wand-011 | UG1 | no | yes | no | 1.69998 | 2.88 | 0.319997 | 4.60795 | 4.60795 | 0.921591 | 0.921591
Wand-010 | UG1 | no | yes | no | 1.95077 | 2.88 | 0.410153 | 5.90621 | 5.90621 | 1.18124 | 1.18124
Wand-009 | UG1 | no | yes | no | 4.77701 | 2.88 | 0.243404 | 13.1818 | 5.83579 | 2.63636 | 1.16715
Wand-008 | UG1 | no | yes | no | 2.0178 | 2.88 | 0.18356 | 5.81126 | 3.50126 | 1.16225 | 0.700252
Wand-006 | UG1 | yes | yes | no | 4.97724 | 2.88 | 0.995448 | 14.3344 | 14.3344 | 2.86689 | 2.86689
Wand-005 | UG1 | no | yes | no | 2.3178 | 2.88 | 0.18356 | 5.81126 | 3.50126 | 1.16225 | 0.700252
Wand-004 | UG1 | no | yes | no | 3.72114 | 2.88 | 0.744228 | 10.7169 | 10.7169 | 2.14338 | 2.14338
Wand-003 | UG1 | no | yes | no | 2.65921 | 2.88 | 0.551843 | 7.94654 | 7.94654 | 1.58931 | 1.58931
Wand-003 | UG1 | yes | yes | yes | 5.9853 | 2.88 | 1.10709 | 15.9421 | 15.9421 | 3.18841 | 3.18841
Wand-003 | UG1 | yes | yes | yes | 1.01133 | 3.08 | 0.202265 | 3.07386 | 3.07386 | 0.614772 | 0.614772
Wand-002 | UG1 | yes | yes | yes | 5.67652 | 2.88 | 1.15532 | 16.6366 | 16.6366 | 3.32732 | 3.32732
Wand-007 | UG1 | yes | yes | yes | 3.87771 | 2.43 | 0.15372 | 9.43293 | 1.94013 | 1.88659 | 0.388026
Wand-003 | EG | yes | yes | no | 1.5961 | 2.76 | 0.0882194 | 4.41903 | 1.43783 | 0.883806 | 0.287566
Wand-003 | EG | yes | yes | no | 0.550614 | 2.76 | 0.110123 | 1.51969 | 1.51969 | 0.303939 | 0.303939
Wand-003 | EG | yes | yes | no | 0.755381 | 2.76 | 0.162076 | 2.23665 | 2.23665 | 0.44733 | 0.44733
Wand-003 | EG | yes | yes | no | 1.81805 | 2.76 | 0.370109 | 5.10751 | 5.10751 | 1.0215 | 1.0215
Wand-003 | EG | yes | yes | no | 1.69615 | 2.76 | 0.32023 | 4.41917 | 4.41917 | 0.883834 | 0.883834
Wand-003 | EG | no | yes | no | 6.71385 | 2.76 | 1.16677 | 18.8338 | 16.5915 | 3.76677 | 3.3183
Wand-006 | EG | yes | no | yes | 1.75253 | 0.196915 | 0.205974 | 0.101118 | 0.101118 | 0.0202234 | 0.0202234
Wand-006 | EG | yes | no | yes | 3.09753 | 0.2 | 0.619507 | 0.619507 | 0.619507 | 0.123901 | 0.123901
Wand-010 | EG | no | no | yes | 1.37901 | 1.4 | 0.311801 | 2.18261 | 2.18261 | 0.436522 | 0.436522
Wand-003 | OG1 | yes | yes | no | 0.550614 | 2.76 | 0.110123 | 1.51969 | 1.51969 | 0.303939 | 0.303939
Wand-003 | OG1 | yes | yes | no | 0.755381 | 2.76 | 0.162076 | 2.23665 | 2.23665 | 0.44733 | 0.44733
Wand-003 | OG1 | yes | yes | no | 1.85055 | 2.76 | 0.410109 | 5.65951 | 5.65951 | 1.1319 | 1.1319
Wand-003 | OG1 | yes | yes | no | 1.69614 | 2.76 | 0.320229 | 4.41916 | 4.41916 | 0.883832 | 0.883832
Wand-003 | OG1 | yes | yes | no | 1.69614 | 2.76 | 0.0882289 | 4.41916 | 1.43796 | 0.883832 | 0.287592
Wand-003 | OG1 | no | yes | no | 6.71385 | 2.76 | 1.16677 | 18.8338 | 16.5915 | 3.76677 | 3.3183
Wand-003 | DG1 | yes | yes | no | 0.350614 | 2.76 | 0.0701228 | 0.967694 | 0.967694 | 0.193539 | 0.193539
Wand-003 | DG1 | yes | yes | no | 0.755381 | 2.76 | 0.162076 | 2.23665 | 2.23665 | 0.44733 | 0.44733
Wand-003 | DG1 | yes | yes | no | 2.05467 | 2.76 | 0.409934 | 5.65708 | 5.65708 | 1.13142 | 1.13142
Wand-003 | DG1 | no | yes | no | 2.18816 | 2.76 | 0.260632 | 6.32912 | 4.08677 | 1.26582 | 0.817354
Wand-003 | DG1 | yes | yes | no | 1.59615 | 2.76 | 0.0882292 | 4.41916 | 1.43796 | 0.883833 | 0.287593
Wand-003 | DG2 | yes | yes | no | 1.79529 | 2.49 | 0.128058 | 4.48272 | 1.59432 | 0.896545 | 0.318865
Wand-003 | DG2 | yes | yes | no | 3.41231 | 3.18 | 0.504463 | 8.86231 | 6.84646 | 1.77246 | 1.36929

# IfcWall: Stahlbeton Wand 250 (12)
Material: Stahlbeton Wand
Qto_WallBaseQuantities - Width: 0.25 m; Stahlbeton Wand, Width: 0.25 m
Name | In | Status | Length (m) | Height (m) | GrossFootprintArea (m2) = NetFootprintArea (m2) | GrossSideArea (m2) = NetSideArea (m2) | GrossVolume (m3) = NetVolume (m3)
Wand-010 | UG2 | Neu | 2.05075 | 0.595 | 0.46269 | 0.97815 | 0.219862 | Pset_WallCommon - Brandwiderstand: REI 90; Compartmentation: no; ExtendToStructure: no; FireRating: REI 90; IsExternal: yes; LoadBearing: yes; SurfaceSpreadOfFlame: A1; ThermalTransmittance: 2.84
Wand-004 | UG1 | Neu | 3.60627 | 2.9038 | 0.891679 | 9.11743 | 2.27902 | Pset_WallCommon - Brandwiderstand: REI 90; Compartmentation: yes; ExtendToStructure: yes; FireRating: REI 90; IsExternal: yes; LoadBearing: yes; SurfaceSpreadOfFlame: A1; ThermalTransmittance: 2.84
Wand-003 | UG1 | Neu | 18.645 | 2.4 | 4.7159 | 45.2727 | 11.3182 | Pset_WallCommon - Brandwiderstand: REI 90; Compartmentation: yes; ExtendToStructure: yes; FireRating: REI 90; IsExternal: yes; LoadBearing: yes; SurfaceSpreadOfFlame: A1; ThermalTransmittance: 2.84
Wand-004 | UG1 | Neu | 2.04107 | 3.08 | 0.506041 | 3.2158 | 1.53422 | Pset_WallCommon - Brandwiderstand: REI 90; Compartmentation: yes; ExtendToStructure: yes; FireRating: REI 90; IsExternal: yes; LoadBearing: yes; SurfaceSpreadOfFlame: A1; ThermalTransmittance: 2.84
Wand-008 | EG | EXISTING | 6.27422 | 0.52 | 1.6186 | 3.36668 | 0.84167
Wand-009 | EG | EXISTING | 4.87203 | 0.52 | 1.18673 | 2.4684 | 0.617101
Wand-007 | EG | EXISTING | 2.54368 | 0.52 | 0.614814 | 1.27881 | 0.319703
Wand-006 | EG | EXISTING | 4.0742 | 0.52 | 1.01873 | 2.11896 | 0.529739
Wand-005 | EG | EXISTING | 22.9207 | 0.52 | 5.74236 | 11.9441 | 2.98603
Wand-004 | EG | EXISTING | 27.9575 | 0.52 | 6.98936 | 14.5379 | 3.63447
Wand-003 | EG | EXISTING | 24.8477 | 0.52 | 6.24318 | 12.9858 | 3.24645
Wand-008 | EG | EXISTING | 7.41763 | 0.52 | 1.87317 | 3.8962 | 0.97405

# IfcWall: Stahlbeton Wand Garage 550 (3)
In: UG1
Material: Stahlbeton Wand Garage
Pset_WallCommon - Brandwiderstand: REI 90; Compartmentation: no; ExtendToStructure: yes; FireRating: REI 90; IsExternal: yes; LoadBearing: yes; Status: Neu; SurfaceSpreadOfFlame: A1; ThermalTransmittance: 2.84
Qto_WallBaseQuantities - Height: 3.08 m; Width: 0.55 m; Stahlbeton Wand Garage, Width: 0.55 m
Name | Length (m) | GrossFootprintArea (m2) = NetFootprintArea (m2) | GrossSideArea (m2) = NetSideArea (m2) | GrossVolume (m3) = NetVolume (m3)
Wand-004 | 22.4537 | 12.0294 | 33.3958 | 37.0505
Wand-003 | 3.79328 | 2.00434 | 11.2243 | 6.17336
Wand-002 | 18.7706 | 10.5884 | 59.2951 | 32.6123

# IfcWindow: 1-Flügelfenster 26, Fenster-001
In: EG
Type - PartitioningType: SINGLE_PANEL
OverallHeight: 1.5 m; OverallWidth: 0.7 m
Pset_WindowCommon - FireExit: no; FireRating: EI 30; IsExternal: yes; SmokeStop: no; Status: Neu; ThermalTransmittance: 0.5
ZDB_WindowData - MainWindow: no; Orientation: vertical
Qto_WindowBaseQuantities - Height: 1.5 m; Width: 0.7 m; Perimeter: 4.4 m; Area: 1.05 m2

# IfcWindow: 2-Flügelfenster 1+1 26, Fenster-001
In: EG
Type - PartitioningType: DOUBLE_PANEL_VERTICAL
OverallHeight: 1.5 m; OverallWidth: 1.9 m
Pset_WindowCommon - FireExit: no; FireRating: EI 30; IsExternal: yes; SmokeStop: no; Status: Neu; ThermalTransmittance: 0.5
ZDB_WindowData - MainWindow: yes; Orientation: vertical
Qto_WindowBaseQuantities - Height: 1.5 m; Width: 1.9 m; Perimeter: 6.8 m; Area: 2.85 m2

# IfcWindow: Dachfenster Wendeflügel 26 (8)
Pset_WindowCommon - FireExit: no; FireRating: EI 30; IsExternal: yes; SmokeStop: no; Status: Neu
ZDB_WindowData - MainWindow: yes; Orientation: tilted
Name | In | OverallHeight (m) = Height (m) | OverallWidth (m) = Width (m) | ThermalTransmittance | Perimeter (m) | Area (m2)
DFenst-002 | DG1 | 1.4 | 1.14476 | 0.6 | 5.08951 | 1.60266
DFenst-002 | DG1 | 1.4 | 1.14 | 0.6 | 5.08 | 1.596
2 x DFenst-002 | DG1 | 1.6 | 1 | 0 | 5.2 | 1.6
2 x DFenst-002 | DG2 | 1.4 | 1.14 | 0.6 | 5.08 | 1.596
2 x DFenst-002 | DG2 | 1.6 | 1 | 0.6 | 5.2 | 1.6

# IfcWindow: Kombi-Fenster 1-Fl 26 (24)
Pset_WindowCommon - FireExit: no; FireRating: EI 30; IsExternal: yes; SmokeStop: no; Status: Neu
ZDB_WindowData - Orientation: vertical
Name | In | OverallHeight (m) = Height (m) | OverallWidth (m) = Width (m) | ThermalTransmittance | MainWindow | Perimeter (m) | Area (m2)
5 x Fenster-001 | OG1 | 2.26 | 1.8 | 0.58 | yes | 8.12 | 4.068
Fenster-001 | OG1 | 2.26 | 1.05 | 0.55 | no | 6.62 | 2.373
3 x Fenster-001 | OG1 | 2.26 | 0.9 | 0.55 | yes | 6.32 | 2.034
2 x Fenster-001 | OG1 | 2.26 | 0.65 | 0.55 | no | 5.82 | 1.469
Fenster-001 | DG1 | 2.26 | 1.05 | 0.55 | no | 6.62 | 2.373
2 x Fenster-001 | DG1 | 2.26 | 0.65 | 0.55 | no | 5.82 | 1.469
3 x Fenster-001 | DG1 | 2.26 | 0.9 | 0.55 | yes | 6.32 | 2.034
3 x Fenster-001 | DG1 | 2.26 | 1.8 | 0.58 | yes | 8.12 | 4.068
Fenster-001 | DG2 | 2 | 1.05 | 0.55 | yes | 6.1 | 2.1
Fenster-001 | DG2 | 2.26 | 1.8 | 0.58 | yes | 8.12 | 4.068
2 x Fenster-001 | DG2 | 2.26 | 0.9 | 0.55 | yes | 6.32 | 2.034

# IfcWindow: Oberlicht Rechteck 26 (2)
In: DA
OverallHeight: 1.09985 m; OverallWidth: 1.09817 m
Pset_WindowCommon - FireExit: no; FireRating: EI 30; IsExternal: yes; SmokeStop: no; Status: Neu; ThermalTransmittance: 0.6
ZDB_WindowData - MainWindow: yes; Orientation: horizontal
Qto_WindowBaseQuantities - Height: 1.09985 m; Width: 1.09817 m; Perimeter: 4.39605 m; Area: 1.20783 m2
